VERSION 5.7 ;
  NOWIREEXTENSIONATPIN ON ;
  DIVIDERCHAR "/" ;
  BUSBITCHARS "[]" ;
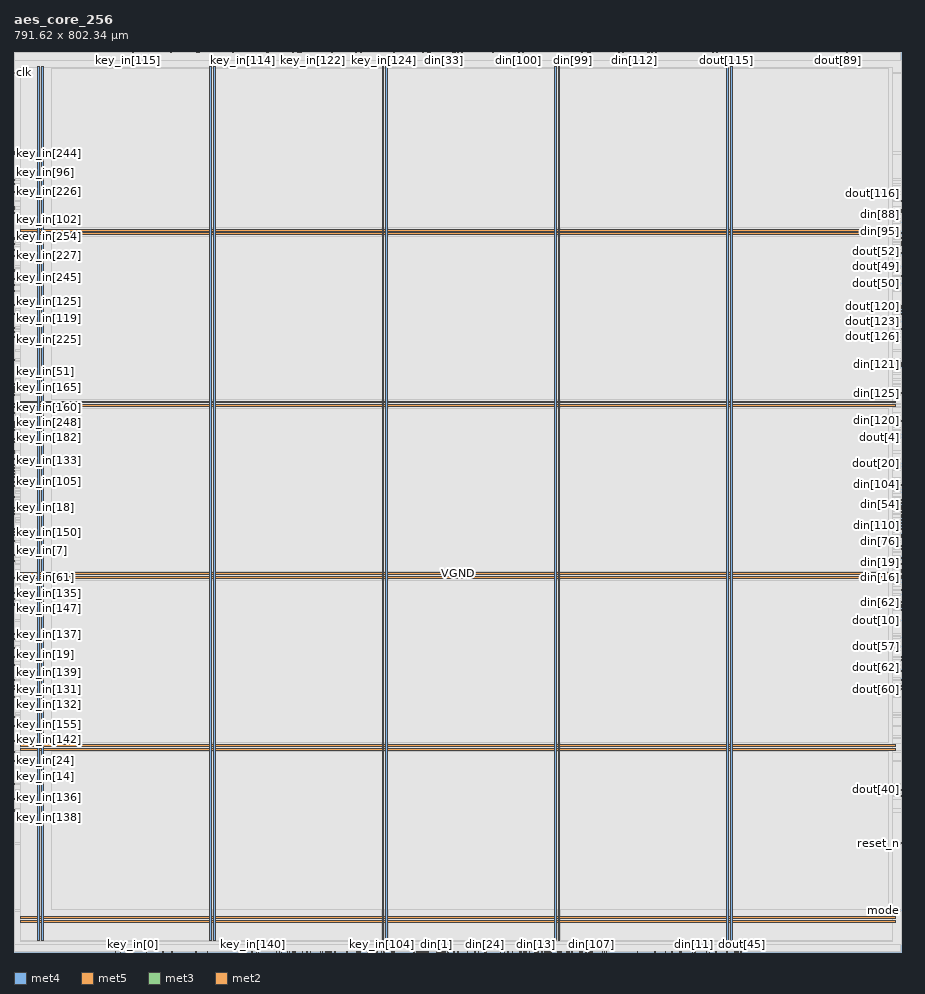
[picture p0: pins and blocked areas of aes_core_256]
MACRO aes_core_256
  CLASS BLOCK ;
  FOREIGN aes_core_256 ;
  ORIGIN 0.000 0.000 ;
  SIZE 791.620 BY 802.340 ;
  PIN VGND
    DIRECTION INOUT ;
    USE GROUND ;
    PORT
      LAYER met4 ;
        RECT 24.340 10.640 25.940 789.040 ;
    END
    PORT
      LAYER met4 ;
        RECT 177.940 10.640 179.540 789.040 ;
    END
    PORT
      LAYER met4 ;
        RECT 331.540 10.640 333.140 789.040 ;
    END
    PORT
      LAYER met4 ;
        RECT 485.140 10.640 486.740 789.040 ;
    END
    PORT
      LAYER met4 ;
        RECT 638.740 10.640 640.340 789.040 ;
    END
    PORT
      LAYER met5 ;
        RECT 5.520 30.030 785.680 31.630 ;
    END
    PORT
      LAYER met5 ;
        RECT 5.520 183.210 785.680 184.810 ;
    END
    PORT
      LAYER met5 ;
        RECT 5.520 336.390 785.680 337.990 ;
    END
    PORT
      LAYER met5 ;
        RECT 5.520 489.570 785.680 491.170 ;
    END
    PORT
      LAYER met5 ;
        RECT 5.520 642.750 785.680 644.350 ;
    END
  END VGND
  PIN VPWR
    DIRECTION INOUT ;
    USE POWER ;
    PORT
      LAYER met4 ;
        RECT 21.040 10.640 22.640 789.040 ;
    END
    PORT
      LAYER met4 ;
        RECT 174.640 10.640 176.240 789.040 ;
    END
    PORT
      LAYER met4 ;
        RECT 328.240 10.640 329.840 789.040 ;
    END
    PORT
      LAYER met4 ;
        RECT 481.840 10.640 483.440 789.040 ;
    END
    PORT
      LAYER met4 ;
        RECT 635.440 10.640 637.040 789.040 ;
    END
    PORT
      LAYER met5 ;
        RECT 5.520 26.730 785.680 28.330 ;
    END
    PORT
      LAYER met5 ;
        RECT 5.520 179.910 785.680 181.510 ;
    END
    PORT
      LAYER met5 ;
        RECT 5.520 333.090 785.680 334.690 ;
    END
    PORT
      LAYER met5 ;
        RECT 5.520 486.270 785.680 487.870 ;
    END
    PORT
      LAYER met5 ;
        RECT 5.520 639.450 785.680 641.050 ;
    END
  END VPWR
  PIN clk
    DIRECTION INPUT ;
    USE SIGNAL ;
    ANTENNAGATEAREA 0.852000 ;
    PORT
      LAYER met3 ;
        RECT 0.000 783.400 0.600 784.000 ;
    END
  END clk
  PIN din[0]
    DIRECTION INPUT ;
    USE SIGNAL ;
    ANTENNAGATEAREA 0.213000 ;
    PORT
      LAYER met2 ;
        RECT 392.010 0.000 392.290 0.280 ;
    END
  END din[0]
  PIN din[100]
    DIRECTION INPUT ;
    USE SIGNAL ;
    ANTENNAGATEAREA 0.213000 ;
    PORT
      LAYER met2 ;
        RECT 449.970 802.060 450.250 802.340 ;
    END
  END din[100]
  PIN din[101]
    DIRECTION INPUT ;
    USE SIGNAL ;
    ANTENNAGATEAREA 0.213000 ;
    PORT
      LAYER met2 ;
        RECT 418.690 802.060 418.970 802.340 ;
    END
  END din[101]
  PIN din[102]
    DIRECTION INPUT ;
    USE SIGNAL ;
    ANTENNAGATEAREA 0.213000 ;
    PORT
      LAYER met2 ;
        RECT 431.570 802.060 431.850 802.340 ;
    END
  END din[102]
  PIN din[103]
    DIRECTION INPUT ;
    USE SIGNAL ;
    ANTENNAGATEAREA 0.213000 ;
    PORT
      LAYER met2 ;
        RECT 432.490 802.060 432.770 802.340 ;
    END
  END din[103]
  PIN din[104]
    DIRECTION INPUT ;
    USE SIGNAL ;
    ANTENNAGATEAREA 0.213000 ;
    PORT
      LAYER met3 ;
        RECT 791.020 416.200 791.620 416.800 ;
    END
  END din[104]
  PIN din[105]
    DIRECTION INPUT ;
    USE SIGNAL ;
    ANTENNAGATEAREA 0.213000 ;
    PORT
      LAYER met3 ;
        RECT 791.020 409.400 791.620 410.000 ;
    END
  END din[105]
  PIN din[106]
    DIRECTION INPUT ;
    USE SIGNAL ;
    ANTENNAGATEAREA 0.213000 ;
    PORT
      LAYER met3 ;
        RECT 791.020 394.440 791.620 395.040 ;
    END
  END din[106]
  PIN din[107]
    DIRECTION INPUT ;
    USE SIGNAL ;
    ANTENNAGATEAREA 0.213000 ;
    PORT
      LAYER met2 ;
        RECT 514.370 0.000 514.650 0.280 ;
    END
  END din[107]
  PIN din[108]
    DIRECTION INPUT ;
    USE SIGNAL ;
    ANTENNAGATEAREA 0.213000 ;
    PORT
      LAYER met2 ;
        RECT 478.490 0.000 478.770 0.280 ;
    END
  END din[108]
  PIN din[109]
    DIRECTION INPUT ;
    USE SIGNAL ;
    ANTENNAGATEAREA 0.213000 ;
    PORT
      LAYER met2 ;
        RECT 505.170 0.000 505.450 0.280 ;
    END
  END din[109]
  PIN din[10]
    DIRECTION INPUT ;
    USE SIGNAL ;
    ANTENNAGATEAREA 0.213000 ;
    PORT
      LAYER met2 ;
        RECT 497.810 0.000 498.090 0.280 ;
    END
  END din[10]
  PIN din[110]
    DIRECTION INPUT ;
    USE SIGNAL ;
    ANTENNAGATEAREA 0.213000 ;
    PORT
      LAYER met3 ;
        RECT 791.020 379.480 791.620 380.080 ;
    END
  END din[110]
  PIN din[111]
    DIRECTION INPUT ;
    USE SIGNAL ;
    ANTENNAGATEAREA 0.213000 ;
    PORT
      LAYER met3 ;
        RECT 791.020 380.840 791.620 381.440 ;
    END
  END din[111]
  PIN din[112]
    DIRECTION INPUT ;
    USE SIGNAL ;
    ANTENNAGATEAREA 0.213000 ;
    PORT
      LAYER met2 ;
        RECT 553.010 802.060 553.290 802.340 ;
    END
  END din[112]
  PIN din[113]
    DIRECTION INPUT ;
    USE SIGNAL ;
    ANTENNAGATEAREA 0.213000 ;
    PORT
      LAYER met2 ;
        RECT 528.170 802.060 528.450 802.340 ;
    END
  END din[113]
  PIN din[114]
    DIRECTION INPUT ;
    USE SIGNAL ;
    ANTENNAGATEAREA 0.213000 ;
    PORT
      LAYER met2 ;
        RECT 518.970 802.060 519.250 802.340 ;
    END
  END din[114]
  PIN din[115]
    DIRECTION INPUT ;
    USE SIGNAL ;
    ANTENNAGATEAREA 0.213000 ;
    PORT
      LAYER met2 ;
        RECT 539.210 802.060 539.490 802.340 ;
    END
  END din[115]
  PIN din[116]
    DIRECTION INPUT ;
    USE SIGNAL ;
    ANTENNAGATEAREA 0.213000 ;
    PORT
      LAYER met2 ;
        RECT 511.610 802.060 511.890 802.340 ;
    END
  END din[116]
  PIN din[117]
    DIRECTION INPUT ;
    USE SIGNAL ;
    ANTENNAGATEAREA 0.213000 ;
    PORT
      LAYER met2 ;
        RECT 442.610 802.060 442.890 802.340 ;
    END
  END din[117]
  PIN din[118]
    DIRECTION INPUT ;
    USE SIGNAL ;
    ANTENNAGATEAREA 0.213000 ;
    PORT
      LAYER met2 ;
        RECT 533.690 802.060 533.970 802.340 ;
    END
  END din[118]
  PIN din[119]
    DIRECTION INPUT ;
    USE SIGNAL ;
    ANTENNAGATEAREA 0.213000 ;
    PORT
      LAYER met2 ;
        RECT 444.450 802.060 444.730 802.340 ;
    END
  END din[119]
  PIN din[11]
    DIRECTION INPUT ;
    USE SIGNAL ;
    ANTENNAGATEAREA 0.213000 ;
    PORT
      LAYER met2 ;
        RECT 606.370 0.000 606.650 0.280 ;
    END
  END din[11]
  PIN din[120]
    DIRECTION INPUT ;
    USE SIGNAL ;
    ANTENNAGATEAREA 0.213000 ;
    PORT
      LAYER met3 ;
        RECT 791.020 473.320 791.620 473.920 ;
    END
  END din[120]
  PIN din[121]
    DIRECTION INPUT ;
    USE SIGNAL ;
    ANTENNAGATEAREA 0.213000 ;
    PORT
      LAYER met3 ;
        RECT 791.020 523.640 791.620 524.240 ;
    END
  END din[121]
  PIN din[122]
    DIRECTION INPUT ;
    USE SIGNAL ;
    ANTENNAGATEAREA 0.213000 ;
    PORT
      LAYER met3 ;
        RECT 791.020 461.080 791.620 461.680 ;
    END
  END din[122]
  PIN din[123]
    DIRECTION INPUT ;
    USE SIGNAL ;
    ANTENNAGATEAREA 0.213000 ;
    PORT
      LAYER met2 ;
        RECT 546.570 802.060 546.850 802.340 ;
    END
  END din[123]
  PIN din[124]
    DIRECTION INPUT ;
    USE SIGNAL ;
    ANTENNAGATEAREA 0.213000 ;
    PORT
      LAYER met3 ;
        RECT 791.020 522.280 791.620 522.880 ;
    END
  END din[124]
  PIN din[125]
    DIRECTION INPUT ;
    USE SIGNAL ;
    ANTENNAGATEAREA 0.213000 ;
    PORT
      LAYER met3 ;
        RECT 791.020 497.800 791.620 498.400 ;
    END
  END din[125]
  PIN din[126]
    DIRECTION INPUT ;
    USE SIGNAL ;
    ANTENNAGATEAREA 0.213000 ;
    PORT
      LAYER met2 ;
        RECT 513.450 802.060 513.730 802.340 ;
    END
  END din[126]
  PIN din[127]
    DIRECTION INPUT ;
    USE SIGNAL ;
    ANTENNAGATEAREA 0.213000 ;
    PORT
      LAYER met3 ;
        RECT 791.020 520.920 791.620 521.520 ;
    END
  END din[127]
  PIN din[12]
    DIRECTION INPUT ;
    USE SIGNAL ;
    ANTENNAGATEAREA 0.213000 ;
    PORT
      LAYER met2 ;
        RECT 634.890 0.000 635.170 0.280 ;
    END
  END din[12]
  PIN din[13]
    DIRECTION INPUT ;
    USE SIGNAL ;
    ANTENNAGATEAREA 0.213000 ;
    PORT
      LAYER met2 ;
        RECT 465.610 0.000 465.890 0.280 ;
    END
  END din[13]
  PIN din[14]
    DIRECTION INPUT ;
    USE SIGNAL ;
    ANTENNAGATEAREA 0.213000 ;
    PORT
      LAYER met2 ;
        RECT 493.210 0.000 493.490 0.280 ;
    END
  END din[14]
  PIN din[15]
    DIRECTION INPUT ;
    USE SIGNAL ;
    ANTENNAGATEAREA 0.213000 ;
    PORT
      LAYER met2 ;
        RECT 484.930 0.000 485.210 0.280 ;
    END
  END din[15]
  PIN din[16]
    DIRECTION INPUT ;
    USE SIGNAL ;
    ANTENNAGATEAREA 0.213000 ;
    PORT
      LAYER met3 ;
        RECT 791.020 333.240 791.620 333.840 ;
    END
  END din[16]
  PIN din[17]
    DIRECTION INPUT ;
    USE SIGNAL ;
    ANTENNAGATEAREA 0.213000 ;
    PORT
      LAYER met2 ;
        RECT 473.890 0.000 474.170 0.280 ;
    END
  END din[17]
  PIN din[18]
    DIRECTION INPUT ;
    USE SIGNAL ;
    ANTENNAGATEAREA 0.213000 ;
    PORT
      LAYER met2 ;
        RECT 414.090 0.000 414.370 0.280 ;
    END
  END din[18]
  PIN din[19]
    DIRECTION INPUT ;
    USE SIGNAL ;
    ANTENNAGATEAREA 0.213000 ;
    PORT
      LAYER met3 ;
        RECT 791.020 340.040 791.620 340.640 ;
    END
  END din[19]
  PIN din[1]
    DIRECTION INPUT ;
    USE SIGNAL ;
    ANTENNAGATEAREA 0.213000 ;
    PORT
      LAYER met2 ;
        RECT 376.370 0.000 376.650 0.280 ;
    END
  END din[1]
  PIN din[20]
    DIRECTION INPUT ;
    USE SIGNAL ;
    ANTENNAGATEAREA 0.213000 ;
    PORT
      LAYER met3 ;
        RECT 791.020 345.480 791.620 346.080 ;
    END
  END din[20]
  PIN din[21]
    DIRECTION INPUT ;
    USE SIGNAL ;
    ANTENNAGATEAREA 0.213000 ;
    PORT
      LAYER met2 ;
        RECT 450.890 0.000 451.170 0.280 ;
    END
  END din[21]
  PIN din[22]
    DIRECTION INPUT ;
    USE SIGNAL ;
    ANTENNAGATEAREA 0.213000 ;
    PORT
      LAYER met3 ;
        RECT 791.020 307.400 791.620 308.000 ;
    END
  END din[22]
  PIN din[23]
    DIRECTION INPUT ;
    USE SIGNAL ;
    ANTENNAGATEAREA 0.213000 ;
    PORT
      LAYER met3 ;
        RECT 791.020 350.920 791.620 351.520 ;
    END
  END din[23]
  PIN din[24]
    DIRECTION INPUT ;
    USE SIGNAL ;
    ANTENNAGATEAREA 0.213000 ;
    PORT
      LAYER met2 ;
        RECT 419.610 0.000 419.890 0.280 ;
    END
  END din[24]
  PIN din[25]
    DIRECTION INPUT ;
    USE SIGNAL ;
    ANTENNAGATEAREA 0.213000 ;
    PORT
      LAYER met2 ;
        RECT 410.410 0.000 410.690 0.280 ;
    END
  END din[25]
  PIN din[26]
    DIRECTION INPUT ;
    USE SIGNAL ;
    ANTENNAGATEAREA 0.213000 ;
    PORT
      LAYER met2 ;
        RECT 433.410 0.000 433.690 0.280 ;
    END
  END din[26]
  PIN din[27]
    DIRECTION INPUT ;
    USE SIGNAL ;
    ANTENNAGATEAREA 0.213000 ;
    PORT
      LAYER met2 ;
        RECT 474.810 0.000 475.090 0.280 ;
    END
  END din[27]
  PIN din[28]
    DIRECTION INPUT ;
    USE SIGNAL ;
    ANTENNAGATEAREA 0.213000 ;
    PORT
      LAYER met2 ;
        RECT 459.170 0.000 459.450 0.280 ;
    END
  END din[28]
  PIN din[29]
    DIRECTION INPUT ;
    USE SIGNAL ;
    ANTENNAGATEAREA 0.213000 ;
    PORT
      LAYER met2 ;
        RECT 444.450 0.000 444.730 0.280 ;
    END
  END din[29]
  PIN din[2]
    DIRECTION INPUT ;
    USE SIGNAL ;
    ANTENNAGATEAREA 0.213000 ;
    PORT
      LAYER met2 ;
        RECT 377.290 0.000 377.570 0.280 ;
    END
  END din[2]
  PIN din[30]
    DIRECTION INPUT ;
    USE SIGNAL ;
    ANTENNAGATEAREA 0.213000 ;
    PORT
      LAYER met2 ;
        RECT 378.210 0.000 378.490 0.280 ;
    END
  END din[30]
  PIN din[31]
    DIRECTION INPUT ;
    USE SIGNAL ;
    ANTENNAGATEAREA 0.213000 ;
    PORT
      LAYER met2 ;
        RECT 386.490 0.000 386.770 0.280 ;
    END
  END din[31]
  PIN din[32]
    DIRECTION INPUT ;
    USE SIGNAL ;
    ANTENNAGATEAREA 0.213000 ;
    PORT
      LAYER met3 ;
        RECT 791.020 398.520 791.620 399.120 ;
    END
  END din[32]
  PIN din[33]
    DIRECTION INPUT ;
    USE SIGNAL ;
    ANTENNAGATEAREA 0.213000 ;
    PORT
      LAYER met2 ;
        RECT 382.810 802.060 383.090 802.340 ;
    END
  END din[33]
  PIN din[34]
    DIRECTION INPUT ;
    USE SIGNAL ;
    ANTENNAGATEAREA 0.213000 ;
    PORT
      LAYER met2 ;
        RECT 380.050 802.060 380.330 802.340 ;
    END
  END din[34]
  PIN din[35]
    DIRECTION INPUT ;
    USE SIGNAL ;
    ANTENNAGATEAREA 0.213000 ;
    PORT
      LAYER met3 ;
        RECT 791.020 376.760 791.620 377.360 ;
    END
  END din[35]
  PIN din[36]
    DIRECTION INPUT ;
    USE SIGNAL ;
    ANTENNAGATEAREA 0.213000 ;
    PORT
      LAYER met2 ;
        RECT 392.010 802.060 392.290 802.340 ;
    END
  END din[36]
  PIN din[37]
    DIRECTION INPUT ;
    USE SIGNAL ;
    ANTENNAGATEAREA 0.213000 ;
    PORT
      LAYER met2 ;
        RECT 451.810 0.000 452.090 0.280 ;
    END
  END din[37]
  PIN din[38]
    DIRECTION INPUT ;
    USE SIGNAL ;
    ANTENNAGATEAREA 0.213000 ;
    PORT
      LAYER met2 ;
        RECT 392.930 802.060 393.210 802.340 ;
    END
  END din[38]
  PIN din[39]
    DIRECTION INPUT ;
    USE SIGNAL ;
    ANTENNAGATEAREA 0.213000 ;
    PORT
      LAYER met2 ;
        RECT 400.290 802.060 400.570 802.340 ;
    END
  END din[39]
  PIN din[3]
    DIRECTION INPUT ;
    USE SIGNAL ;
    ANTENNAGATEAREA 0.213000 ;
    PORT
      LAYER met2 ;
        RECT 380.970 0.000 381.250 0.280 ;
    END
  END din[3]
  PIN din[40]
    DIRECTION INPUT ;
    USE SIGNAL ;
    ANTENNAGATEAREA 0.213000 ;
    PORT
      LAYER met2 ;
        RECT 580.610 0.000 580.890 0.280 ;
    END
  END din[40]
  PIN din[41]
    DIRECTION INPUT ;
    USE SIGNAL ;
    ANTENNAGATEAREA 0.213000 ;
    PORT
      LAYER met2 ;
        RECT 555.770 0.000 556.050 0.280 ;
    END
  END din[41]
  PIN din[42]
    DIRECTION INPUT ;
    USE SIGNAL ;
    ANTENNAGATEAREA 0.213000 ;
    PORT
      LAYER met2 ;
        RECT 528.170 0.000 528.450 0.280 ;
    END
  END din[42]
  PIN din[43]
    DIRECTION INPUT ;
    USE SIGNAL ;
    ANTENNAGATEAREA 0.213000 ;
    PORT
      LAYER met2 ;
        RECT 604.530 0.000 604.810 0.280 ;
    END
  END din[43]
  PIN din[44]
    DIRECTION INPUT ;
    USE SIGNAL ;
    ANTENNAGATEAREA 0.213000 ;
    PORT
      LAYER met2 ;
        RECT 594.410 0.000 594.690 0.280 ;
    END
  END din[44]
  PIN din[45]
    DIRECTION INPUT ;
    USE SIGNAL ;
    ANTENNAGATEAREA 0.213000 ;
    PORT
      LAYER met2 ;
        RECT 617.410 0.000 617.690 0.280 ;
    END
  END din[45]
  PIN din[46]
    DIRECTION INPUT ;
    USE SIGNAL ;
    ANTENNAGATEAREA 0.213000 ;
    PORT
      LAYER met2 ;
        RECT 494.130 0.000 494.410 0.280 ;
    END
  END din[46]
  PIN din[47]
    DIRECTION INPUT ;
    USE SIGNAL ;
    ANTENNAGATEAREA 0.213000 ;
    PORT
      LAYER met2 ;
        RECT 495.050 0.000 495.330 0.280 ;
    END
  END din[47]
  PIN din[48]
    DIRECTION INPUT ;
    USE SIGNAL ;
    ANTENNAGATEAREA 0.213000 ;
    PORT
      LAYER met2 ;
        RECT 564.970 802.060 565.250 802.340 ;
    END
  END din[48]
  PIN din[49]
    DIRECTION INPUT ;
    USE SIGNAL ;
    ANTENNAGATEAREA 0.213000 ;
    PORT
      LAYER met3 ;
        RECT 791.020 378.120 791.620 378.720 ;
    END
  END din[49]
  PIN din[4]
    DIRECTION INPUT ;
    USE SIGNAL ;
    ANTENNAGATEAREA 0.213000 ;
    PORT
      LAYER met2 ;
        RECT 420.530 0.000 420.810 0.280 ;
    END
  END din[4]
  PIN din[50]
    DIRECTION INPUT ;
    USE SIGNAL ;
    ANTENNAGATEAREA 0.213000 ;
    PORT
      LAYER met3 ;
        RECT 791.020 525.000 791.620 525.600 ;
    END
  END din[50]
  PIN din[51]
    DIRECTION INPUT ;
    USE SIGNAL ;
    ANTENNAGATEAREA 0.213000 ;
    PORT
      LAYER met3 ;
        RECT 791.020 383.560 791.620 384.160 ;
    END
  END din[51]
  PIN din[52]
    DIRECTION INPUT ;
    USE SIGNAL ;
    ANTENNAGATEAREA 0.213000 ;
    PORT
      LAYER met2 ;
        RECT 576.010 802.060 576.290 802.340 ;
    END
  END din[52]
  PIN din[53]
    DIRECTION INPUT ;
    USE SIGNAL ;
    ANTENNAGATEAREA 0.213000 ;
    PORT
      LAYER met3 ;
        RECT 791.020 399.880 791.620 400.480 ;
    END
  END din[53]
  PIN din[54]
    DIRECTION INPUT ;
    USE SIGNAL ;
    ANTENNAGATEAREA 0.213000 ;
    PORT
      LAYER met3 ;
        RECT 791.020 391.720 791.620 392.320 ;
    END
  END din[54]
  PIN din[55]
    DIRECTION INPUT ;
    USE SIGNAL ;
    ANTENNAGATEAREA 0.213000 ;
    PORT
      LAYER met2 ;
        RECT 542.890 802.060 543.170 802.340 ;
    END
  END din[55]
  PIN din[56]
    DIRECTION INPUT ;
    USE SIGNAL ;
    ANTENNAGATEAREA 0.213000 ;
    PORT
      LAYER met2 ;
        RECT 625.690 0.000 625.970 0.280 ;
    END
  END din[56]
  PIN din[57]
    DIRECTION INPUT ;
    USE SIGNAL ;
    ANTENNAGATEAREA 0.213000 ;
    PORT
      LAYER met2 ;
        RECT 524.490 0.000 524.770 0.280 ;
    END
  END din[57]
  PIN din[58]
    DIRECTION INPUT ;
    USE SIGNAL ;
    ANTENNAGATEAREA 0.213000 ;
    PORT
      LAYER met2 ;
        RECT 526.330 0.000 526.610 0.280 ;
    END
  END din[58]
  PIN din[59]
    DIRECTION INPUT ;
    USE SIGNAL ;
    ANTENNAGATEAREA 0.213000 ;
    PORT
      LAYER met3 ;
        RECT 791.020 352.280 791.620 352.880 ;
    END
  END din[59]
  PIN din[5]
    DIRECTION INPUT ;
    USE SIGNAL ;
    ANTENNAGATEAREA 0.213000 ;
    PORT
      LAYER met2 ;
        RECT 437.090 0.000 437.370 0.280 ;
    END
  END din[5]
  PIN din[60]
    DIRECTION INPUT ;
    USE SIGNAL ;
    ANTENNAGATEAREA 0.213000 ;
    PORT
      LAYER met2 ;
        RECT 512.530 0.000 512.810 0.280 ;
    END
  END din[60]
  PIN din[61]
    DIRECTION INPUT ;
    USE SIGNAL ;
    ANTENNAGATEAREA 0.213000 ;
    PORT
      LAYER met2 ;
        RECT 515.290 0.000 515.570 0.280 ;
    END
  END din[61]
  PIN din[62]
    DIRECTION INPUT ;
    USE SIGNAL ;
    ANTENNAGATEAREA 0.213000 ;
    PORT
      LAYER met3 ;
        RECT 791.020 311.480 791.620 312.080 ;
    END
  END din[62]
  PIN din[63]
    DIRECTION INPUT ;
    USE SIGNAL ;
    ANTENNAGATEAREA 0.213000 ;
    PORT
      LAYER met2 ;
        RECT 509.770 0.000 510.050 0.280 ;
    END
  END din[63]
  PIN din[64]
    DIRECTION INPUT ;
    USE SIGNAL ;
    ANTENNAGATEAREA 0.213000 ;
    PORT
      LAYER met2 ;
        RECT 414.090 802.060 414.370 802.340 ;
    END
  END din[64]
  PIN din[65]
    DIRECTION INPUT ;
    USE SIGNAL ;
    ANTENNAGATEAREA 0.213000 ;
    PORT
      LAYER met2 ;
        RECT 405.810 802.060 406.090 802.340 ;
    END
  END din[65]
  PIN din[66]
    DIRECTION INPUT ;
    USE SIGNAL ;
    ANTENNAGATEAREA 0.213000 ;
    PORT
      LAYER met2 ;
        RECT 413.170 802.060 413.450 802.340 ;
    END
  END din[66]
  PIN din[67]
    DIRECTION INPUT ;
    USE SIGNAL ;
    ANTENNAGATEAREA 0.213000 ;
    PORT
      LAYER met2 ;
        RECT 403.050 802.060 403.330 802.340 ;
    END
  END din[67]
  PIN din[68]
    DIRECTION INPUT ;
    USE SIGNAL ;
    ANTENNAGATEAREA 0.213000 ;
    PORT
      LAYER met2 ;
        RECT 438.930 802.060 439.210 802.340 ;
    END
  END din[68]
  PIN din[69]
    DIRECTION INPUT ;
    USE SIGNAL ;
    ANTENNAGATEAREA 0.213000 ;
    PORT
      LAYER met2 ;
        RECT 436.170 802.060 436.450 802.340 ;
    END
  END din[69]
  PIN din[6]
    DIRECTION INPUT ;
    USE SIGNAL ;
    ANTENNAGATEAREA 0.213000 ;
    PORT
      LAYER met2 ;
        RECT 379.130 0.000 379.410 0.280 ;
    END
  END din[6]
  PIN din[70]
    DIRECTION INPUT ;
    USE SIGNAL ;
    ANTENNAGATEAREA 0.213000 ;
    PORT
      LAYER met2 ;
        RECT 416.850 802.060 417.130 802.340 ;
    END
  END din[70]
  PIN din[71]
    DIRECTION INPUT ;
    USE SIGNAL ;
    ANTENNAGATEAREA 0.213000 ;
    PORT
      LAYER met2 ;
        RECT 426.970 802.060 427.250 802.340 ;
    END
  END din[71]
  PIN din[72]
    DIRECTION INPUT ;
    USE SIGNAL ;
    ANTENNAGATEAREA 0.213000 ;
    PORT
      LAYER met2 ;
        RECT 455.490 0.000 455.770 0.280 ;
    END
  END din[72]
  PIN din[73]
    DIRECTION INPUT ;
    USE SIGNAL ;
    ANTENNAGATEAREA 0.213000 ;
    PORT
      LAYER met3 ;
        RECT 791.020 386.280 791.620 386.880 ;
    END
  END din[73]
  PIN din[74]
    DIRECTION INPUT ;
    USE SIGNAL ;
    ANTENNAGATEAREA 0.213000 ;
    PORT
      LAYER met3 ;
        RECT 791.020 382.200 791.620 382.800 ;
    END
  END din[74]
  PIN din[75]
    DIRECTION INPUT ;
    USE SIGNAL ;
    ANTENNAGATEAREA 0.213000 ;
    PORT
      LAYER met3 ;
        RECT 791.020 402.600 791.620 403.200 ;
    END
  END din[75]
  PIN din[76]
    DIRECTION INPUT ;
    USE SIGNAL ;
    ANTENNAGATEAREA 0.213000 ;
    PORT
      LAYER met3 ;
        RECT 791.020 372.680 791.620 373.280 ;
    END
  END din[76]
  PIN din[77]
    DIRECTION INPUT ;
    USE SIGNAL ;
    ANTENNAGATEAREA 0.213000 ;
    PORT
      LAYER met2 ;
        RECT 492.290 0.000 492.570 0.280 ;
    END
  END din[77]
  PIN din[78]
    DIRECTION INPUT ;
    USE SIGNAL ;
    ANTENNAGATEAREA 0.213000 ;
    PORT
      LAYER met2 ;
        RECT 463.770 0.000 464.050 0.280 ;
    END
  END din[78]
  PIN din[79]
    DIRECTION INPUT ;
    USE SIGNAL ;
    ANTENNAGATEAREA 0.213000 ;
    PORT
      LAYER met2 ;
        RECT 472.970 0.000 473.250 0.280 ;
    END
  END din[79]
  PIN din[7]
    DIRECTION INPUT ;
    USE SIGNAL ;
    ANTENNAGATEAREA 0.213000 ;
    PORT
      LAYER met2 ;
        RECT 380.050 0.000 380.330 0.280 ;
    END
  END din[7]
  PIN din[80]
    DIRECTION INPUT ;
    USE SIGNAL ;
    ANTENNAGATEAREA 0.213000 ;
    PORT
      LAYER met2 ;
        RECT 560.370 802.060 560.650 802.340 ;
    END
  END din[80]
  PIN din[81]
    DIRECTION INPUT ;
    USE SIGNAL ;
    ANTENNAGATEAREA 0.213000 ;
    PORT
      LAYER met2 ;
        RECT 543.810 802.060 544.090 802.340 ;
    END
  END din[81]
  PIN din[82]
    DIRECTION INPUT ;
    USE SIGNAL ;
    ANTENNAGATEAREA 0.213000 ;
    PORT
      LAYER met2 ;
        RECT 557.610 802.060 557.890 802.340 ;
    END
  END din[82]
  PIN din[83]
    DIRECTION INPUT ;
    USE SIGNAL ;
    ANTENNAGATEAREA 0.213000 ;
    PORT
      LAYER met2 ;
        RECT 558.530 802.060 558.810 802.340 ;
    END
  END din[83]
  PIN din[84]
    DIRECTION INPUT ;
    USE SIGNAL ;
    ANTENNAGATEAREA 0.213000 ;
    PORT
      LAYER met2 ;
        RECT 547.490 802.060 547.770 802.340 ;
    END
  END din[84]
  PIN din[85]
    DIRECTION INPUT ;
    USE SIGNAL ;
    ANTENNAGATEAREA 0.213000 ;
    PORT
      LAYER met2 ;
        RECT 472.050 802.060 472.330 802.340 ;
    END
  END din[85]
  PIN din[86]
    DIRECTION INPUT ;
    USE SIGNAL ;
    ANTENNAGATEAREA 0.213000 ;
    PORT
      LAYER met2 ;
        RECT 559.450 802.060 559.730 802.340 ;
    END
  END din[86]
  PIN din[87]
    DIRECTION INPUT ;
    USE SIGNAL ;
    ANTENNAGATEAREA 0.213000 ;
    PORT
      LAYER met2 ;
        RECT 556.690 802.060 556.970 802.340 ;
    END
  END din[87]
  PIN din[88]
    DIRECTION INPUT ;
    USE SIGNAL ;
    ANTENNAGATEAREA 0.213000 ;
    PORT
      LAYER met3 ;
        RECT 791.020 650.120 791.620 650.720 ;
    END
  END din[88]
  PIN din[89]
    DIRECTION INPUT ;
    USE SIGNAL ;
    ANTENNAGATEAREA 0.213000 ;
    PORT
      LAYER met2 ;
        RECT 587.050 802.060 587.330 802.340 ;
    END
  END din[89]
  PIN din[8]
    DIRECTION INPUT ;
    USE SIGNAL ;
    ANTENNAGATEAREA 0.213000 ;
    PORT
      LAYER met2 ;
        RECT 476.650 0.000 476.930 0.280 ;
    END
  END din[8]
  PIN din[90]
    DIRECTION INPUT ;
    USE SIGNAL ;
    ANTENNAGATEAREA 0.213000 ;
    PORT
      LAYER met2 ;
        RECT 582.450 802.060 582.730 802.340 ;
    END
  END din[90]
  PIN din[91]
    DIRECTION INPUT ;
    USE SIGNAL ;
    ANTENNAGATEAREA 0.213000 ;
    PORT
      LAYER met2 ;
        RECT 568.650 802.060 568.930 802.340 ;
    END
  END din[91]
  PIN din[92]
    DIRECTION INPUT ;
    USE SIGNAL ;
    ANTENNAGATEAREA 0.213000 ;
    PORT
      LAYER met3 ;
        RECT 791.020 659.640 791.620 660.240 ;
    END
  END din[92]
  PIN din[93]
    DIRECTION INPUT ;
    USE SIGNAL ;
    ANTENNAGATEAREA 0.213000 ;
    PORT
      LAYER met3 ;
        RECT 791.020 661.000 791.620 661.600 ;
    END
  END din[93]
  PIN din[94]
    DIRECTION INPUT ;
    USE SIGNAL ;
    ANTENNAGATEAREA 0.213000 ;
    PORT
      LAYER met2 ;
        RECT 565.890 802.060 566.170 802.340 ;
    END
  END din[94]
  PIN din[95]
    DIRECTION INPUT ;
    USE SIGNAL ;
    ANTENNAGATEAREA 0.213000 ;
    PORT
      LAYER met3 ;
        RECT 791.020 641.960 791.620 642.560 ;
    END
  END din[95]
  PIN din[96]
    DIRECTION INPUT ;
    USE SIGNAL ;
    ANTENNAGATEAREA 0.213000 ;
    PORT
      LAYER met2 ;
        RECT 470.210 802.060 470.490 802.340 ;
    END
  END din[96]
  PIN din[97]
    DIRECTION INPUT ;
    USE SIGNAL ;
    ANTENNAGATEAREA 0.213000 ;
    PORT
      LAYER met2 ;
        RECT 453.650 802.060 453.930 802.340 ;
    END
  END din[97]
  PIN din[98]
    DIRECTION INPUT ;
    USE SIGNAL ;
    ANTENNAGATEAREA 0.213000 ;
    PORT
      LAYER met2 ;
        RECT 458.250 802.060 458.530 802.340 ;
    END
  END din[98]
  PIN din[99]
    DIRECTION INPUT ;
    USE SIGNAL ;
    ANTENNAGATEAREA 0.213000 ;
    PORT
      LAYER met2 ;
        RECT 497.810 802.060 498.090 802.340 ;
    END
  END din[99]
  PIN din[9]
    DIRECTION INPUT ;
    USE SIGNAL ;
    ANTENNAGATEAREA 0.213000 ;
    PORT
      LAYER met2 ;
        RECT 475.730 0.000 476.010 0.280 ;
    END
  END din[9]
  PIN done
    DIRECTION OUTPUT ;
    USE SIGNAL ;
    ANTENNADIFFAREA 0.702900 ;
    PORT
      LAYER met2 ;
        RECT 395.690 0.000 395.970 0.280 ;
    END
  END done
  PIN dout[0]
    DIRECTION OUTPUT ;
    USE SIGNAL ;
    ANTENNADIFFAREA 0.702900 ;
    PORT
      LAYER met2 ;
        RECT 355.210 802.060 355.490 802.340 ;
    END
  END dout[0]
  PIN dout[100]
    DIRECTION OUTPUT ;
    USE SIGNAL ;
    ANTENNADIFFAREA 0.702900 ;
    PORT
      LAYER met2 ;
        RECT 415.930 802.060 416.210 802.340 ;
    END
  END dout[100]
  PIN dout[101]
    DIRECTION OUTPUT ;
    USE SIGNAL ;
    ANTENNADIFFAREA 0.702900 ;
    PORT
      LAYER met2 ;
        RECT 521.730 802.060 522.010 802.340 ;
    END
  END dout[101]
  PIN dout[102]
    DIRECTION OUTPUT ;
    USE SIGNAL ;
    ANTENNADIFFAREA 0.702900 ;
    PORT
      LAYER met2 ;
        RECT 404.890 802.060 405.170 802.340 ;
    END
  END dout[102]
  PIN dout[103]
    DIRECTION OUTPUT ;
    USE SIGNAL ;
    ANTENNADIFFAREA 0.702900 ;
    PORT
      LAYER met2 ;
        RECT 409.490 802.060 409.770 802.340 ;
    END
  END dout[103]
  PIN dout[104]
    DIRECTION OUTPUT ;
    USE SIGNAL ;
    ANTENNADIFFAREA 0.702900 ;
    PORT
      LAYER met3 ;
        RECT 791.020 369.960 791.620 370.560 ;
    END
  END dout[104]
  PIN dout[105]
    DIRECTION OUTPUT ;
    USE SIGNAL ;
    ANTENNADIFFAREA 0.702900 ;
    PORT
      LAYER met3 ;
        RECT 791.020 280.200 791.620 280.800 ;
    END
  END dout[105]
  PIN dout[106]
    DIRECTION OUTPUT ;
    USE SIGNAL ;
    ANTENNADIFFAREA 0.702900 ;
    PORT
      LAYER met3 ;
        RECT 791.020 371.320 791.620 371.920 ;
    END
  END dout[106]
  PIN dout[107]
    DIRECTION OUTPUT ;
    USE SIGNAL ;
    ANTENNADIFFAREA 0.702900 ;
    PORT
      LAYER met2 ;
        RECT 644.090 0.000 644.370 0.280 ;
    END
  END dout[107]
  PIN dout[108]
    DIRECTION OUTPUT ;
    USE SIGNAL ;
    ANTENNADIFFAREA 0.702900 ;
    PORT
      LAYER met2 ;
        RECT 504.250 0.000 504.530 0.280 ;
    END
  END dout[108]
  PIN dout[109]
    DIRECTION OUTPUT ;
    USE SIGNAL ;
    ANTENNADIFFAREA 0.702900 ;
    PORT
      LAYER met2 ;
        RECT 506.090 0.000 506.370 0.280 ;
    END
  END dout[109]
  PIN dout[10]
    DIRECTION OUTPUT ;
    USE SIGNAL ;
    ANTENNADIFFAREA 0.702900 ;
    PORT
      LAYER met3 ;
        RECT 791.020 295.160 791.620 295.760 ;
    END
  END dout[10]
  PIN dout[110]
    DIRECTION OUTPUT ;
    USE SIGNAL ;
    ANTENNADIFFAREA 0.702900 ;
    PORT
      LAYER met3 ;
        RECT 791.020 359.080 791.620 359.680 ;
    END
  END dout[110]
  PIN dout[111]
    DIRECTION OUTPUT ;
    USE SIGNAL ;
    ANTENNADIFFAREA 0.702900 ;
    PORT
      LAYER met3 ;
        RECT 791.020 361.800 791.620 362.400 ;
    END
  END dout[111]
  PIN dout[112]
    DIRECTION OUTPUT ;
    USE SIGNAL ;
    ANTENNADIFFAREA 0.702900 ;
    PORT
      LAYER met2 ;
        RECT 522.650 802.060 522.930 802.340 ;
    END
  END dout[112]
  PIN dout[113]
    DIRECTION OUTPUT ;
    USE SIGNAL ;
    ANTENNADIFFAREA 0.702900 ;
    PORT
      LAYER met2 ;
        RECT 622.930 802.060 623.210 802.340 ;
    END
  END dout[113]
  PIN dout[114]
    DIRECTION OUTPUT ;
    USE SIGNAL ;
    ANTENNADIFFAREA 0.702900 ;
    PORT
      LAYER met2 ;
        RECT 530.930 802.060 531.210 802.340 ;
    END
  END dout[114]
  PIN dout[115]
    DIRECTION OUTPUT ;
    USE SIGNAL ;
    ANTENNADIFFAREA 0.702900 ;
    PORT
      LAYER met2 ;
        RECT 634.890 802.060 635.170 802.340 ;
    END
  END dout[115]
  PIN dout[116]
    DIRECTION OUTPUT ;
    USE SIGNAL ;
    ANTENNADIFFAREA 0.702900 ;
    PORT
      LAYER met3 ;
        RECT 791.020 669.160 791.620 669.760 ;
    END
  END dout[116]
  PIN dout[117]
    DIRECTION OUTPUT ;
    USE SIGNAL ;
    ANTENNADIFFAREA 0.702900 ;
    PORT
      LAYER met2 ;
        RECT 637.650 802.060 637.930 802.340 ;
    END
  END dout[117]
  PIN dout[118]
    DIRECTION OUTPUT ;
    USE SIGNAL ;
    ANTENNADIFFAREA 0.702900 ;
    PORT
      LAYER met2 ;
        RECT 626.610 802.060 626.890 802.340 ;
    END
  END dout[118]
  PIN dout[119]
    DIRECTION OUTPUT ;
    USE SIGNAL ;
    ANTENNADIFFAREA 0.702900 ;
    PORT
      LAYER met2 ;
        RECT 635.810 802.060 636.090 802.340 ;
    END
  END dout[119]
  PIN dout[11]
    DIRECTION OUTPUT ;
    USE SIGNAL ;
    ANTENNADIFFAREA 0.702900 ;
    PORT
      LAYER met3 ;
        RECT 791.020 243.480 791.620 244.080 ;
    END
  END dout[11]
  PIN dout[120]
    DIRECTION OUTPUT ;
    USE SIGNAL ;
    ANTENNADIFFAREA 0.702900 ;
    PORT
      LAYER met3 ;
        RECT 791.020 575.320 791.620 575.920 ;
    END
  END dout[120]
  PIN dout[121]
    DIRECTION OUTPUT ;
    USE SIGNAL ;
    ANTENNADIFFAREA 0.702900 ;
    PORT
      LAYER met3 ;
        RECT 791.020 572.600 791.620 573.200 ;
    END
  END dout[121]
  PIN dout[122]
    DIRECTION OUTPUT ;
    USE SIGNAL ;
    ANTENNADIFFAREA 0.702900 ;
    PORT
      LAYER met3 ;
        RECT 791.020 573.960 791.620 574.560 ;
    END
  END dout[122]
  PIN dout[123]
    DIRECTION OUTPUT ;
    USE SIGNAL ;
    ANTENNADIFFAREA 0.702900 ;
    PORT
      LAYER met3 ;
        RECT 791.020 561.720 791.620 562.320 ;
    END
  END dout[123]
  PIN dout[124]
    DIRECTION OUTPUT ;
    USE SIGNAL ;
    ANTENNADIFFAREA 0.702900 ;
    PORT
      LAYER met3 ;
        RECT 791.020 571.240 791.620 571.840 ;
    END
  END dout[124]
  PIN dout[125]
    DIRECTION OUTPUT ;
    USE SIGNAL ;
    ANTENNADIFFAREA 0.702900 ;
    PORT
      LAYER met3 ;
        RECT 791.020 568.520 791.620 569.120 ;
    END
  END dout[125]
  PIN dout[126]
    DIRECTION OUTPUT ;
    USE SIGNAL ;
    ANTENNADIFFAREA 0.702900 ;
    PORT
      LAYER met3 ;
        RECT 791.020 554.920 791.620 555.520 ;
    END
  END dout[126]
  PIN dout[127]
    DIRECTION OUTPUT ;
    USE SIGNAL ;
    ANTENNADIFFAREA 0.702900 ;
    PORT
      LAYER met3 ;
        RECT 791.020 569.880 791.620 570.480 ;
    END
  END dout[127]
  PIN dout[12]
    DIRECTION OUTPUT ;
    USE SIGNAL ;
    ANTENNADIFFAREA 0.702900 ;
    PORT
      LAYER met3 ;
        RECT 791.020 318.280 791.620 318.880 ;
    END
  END dout[12]
  PIN dout[13]
    DIRECTION OUTPUT ;
    USE SIGNAL ;
    ANTENNADIFFAREA 0.702900 ;
    PORT
      LAYER met3 ;
        RECT 791.020 329.160 791.620 329.760 ;
    END
  END dout[13]
  PIN dout[14]
    DIRECTION OUTPUT ;
    USE SIGNAL ;
    ANTENNADIFFAREA 0.702900 ;
    PORT
      LAYER met3 ;
        RECT 791.020 251.640 791.620 252.240 ;
    END
  END dout[14]
  PIN dout[15]
    DIRECTION OUTPUT ;
    USE SIGNAL ;
    ANTENNADIFFAREA 0.702900 ;
    PORT
      LAYER met3 ;
        RECT 791.020 308.760 791.620 309.360 ;
    END
  END dout[15]
  PIN dout[16]
    DIRECTION OUTPUT ;
    USE SIGNAL ;
    ANTENNADIFFAREA 0.702900 ;
    PORT
      LAYER met3 ;
        RECT 791.020 334.600 791.620 335.200 ;
    END
  END dout[16]
  PIN dout[17]
    DIRECTION OUTPUT ;
    USE SIGNAL ;
    ANTENNADIFFAREA 0.702900 ;
    PORT
      LAYER met3 ;
        RECT 791.020 304.680 791.620 305.280 ;
    END
  END dout[17]
  PIN dout[18]
    DIRECTION OUTPUT ;
    USE SIGNAL ;
    ANTENNADIFFAREA 0.702900 ;
    PORT
      LAYER met3 ;
        RECT 791.020 322.360 791.620 322.960 ;
    END
  END dout[18]
  PIN dout[19]
    DIRECTION OUTPUT ;
    USE SIGNAL ;
    ANTENNADIFFAREA 0.702900 ;
    PORT
      LAYER met3 ;
        RECT 791.020 338.680 791.620 339.280 ;
    END
  END dout[19]
  PIN dout[1]
    DIRECTION OUTPUT ;
    USE SIGNAL ;
    ANTENNADIFFAREA 0.702900 ;
    PORT
      LAYER met2 ;
        RECT 403.970 0.000 404.250 0.280 ;
    END
  END dout[1]
  PIN dout[20]
    DIRECTION OUTPUT ;
    USE SIGNAL ;
    ANTENNADIFFAREA 0.702900 ;
    PORT
      LAYER met3 ;
        RECT 791.020 435.240 791.620 435.840 ;
    END
  END dout[20]
  PIN dout[21]
    DIRECTION OUTPUT ;
    USE SIGNAL ;
    ANTENNADIFFAREA 0.702900 ;
    PORT
      LAYER met3 ;
        RECT 791.020 331.880 791.620 332.480 ;
    END
  END dout[21]
  PIN dout[22]
    DIRECTION OUTPUT ;
    USE SIGNAL ;
    ANTENNADIFFAREA 0.702900 ;
    PORT
      LAYER met3 ;
        RECT 791.020 306.040 791.620 306.640 ;
    END
  END dout[22]
  PIN dout[23]
    DIRECTION OUTPUT ;
    USE SIGNAL ;
    ANTENNADIFFAREA 0.702900 ;
    PORT
      LAYER met3 ;
        RECT 791.020 349.560 791.620 350.160 ;
    END
  END dout[23]
  PIN dout[24]
    DIRECTION OUTPUT ;
    USE SIGNAL ;
    ANTENNADIFFAREA 0.702900 ;
    PORT
      LAYER met2 ;
        RECT 471.130 0.000 471.410 0.280 ;
    END
  END dout[24]
  PIN dout[25]
    DIRECTION OUTPUT ;
    USE SIGNAL ;
    ANTENNADIFFAREA 0.702900 ;
    PORT
      LAYER met2 ;
        RECT 464.690 0.000 464.970 0.280 ;
    END
  END dout[25]
  PIN dout[26]
    DIRECTION OUTPUT ;
    USE SIGNAL ;
    ANTENNADIFFAREA 0.702900 ;
    PORT
      LAYER met2 ;
        RECT 466.530 0.000 466.810 0.280 ;
    END
  END dout[26]
  PIN dout[27]
    DIRECTION OUTPUT ;
    USE SIGNAL ;
    ANTENNADIFFAREA 0.702900 ;
    PORT
      LAYER met2 ;
        RECT 477.570 0.000 477.850 0.280 ;
    END
  END dout[27]
  PIN dout[28]
    DIRECTION OUTPUT ;
    USE SIGNAL ;
    ANTENNADIFFAREA 0.702900 ;
    PORT
      LAYER met2 ;
        RECT 470.210 0.000 470.490 0.280 ;
    END
  END dout[28]
  PIN dout[29]
    DIRECTION OUTPUT ;
    USE SIGNAL ;
    ANTENNADIFFAREA 0.702900 ;
    PORT
      LAYER met2 ;
        RECT 454.570 0.000 454.850 0.280 ;
    END
  END dout[29]
  PIN dout[2]
    DIRECTION OUTPUT ;
    USE SIGNAL ;
    ANTENNADIFFAREA 0.702900 ;
    PORT
      LAYER met2 ;
        RECT 387.410 0.000 387.690 0.280 ;
    END
  END dout[2]
  PIN dout[30]
    DIRECTION OUTPUT ;
    USE SIGNAL ;
    ANTENNADIFFAREA 0.702900 ;
    PORT
      LAYER met2 ;
        RECT 456.410 0.000 456.690 0.280 ;
    END
  END dout[30]
  PIN dout[31]
    DIRECTION OUTPUT ;
    USE SIGNAL ;
    ANTENNADIFFAREA 0.702900 ;
    PORT
      LAYER met2 ;
        RECT 467.450 0.000 467.730 0.280 ;
    END
  END dout[31]
  PIN dout[32]
    DIRECTION OUTPUT ;
    USE SIGNAL ;
    ANTENNADIFFAREA 0.702900 ;
    PORT
      LAYER met2 ;
        RECT 395.690 802.060 395.970 802.340 ;
    END
  END dout[32]
  PIN dout[33]
    DIRECTION OUTPUT ;
    USE SIGNAL ;
    ANTENNADIFFAREA 0.702900 ;
    PORT
      LAYER met2 ;
        RECT 370.850 802.060 371.130 802.340 ;
    END
  END dout[33]
  PIN dout[34]
    DIRECTION OUTPUT ;
    USE SIGNAL ;
    ANTENNADIFFAREA 0.702900 ;
    PORT
      LAYER met2 ;
        RECT 388.330 802.060 388.610 802.340 ;
    END
  END dout[34]
  PIN dout[35]
    DIRECTION OUTPUT ;
    USE SIGNAL ;
    ANTENNADIFFAREA 0.702900 ;
    PORT
      LAYER met2 ;
        RECT 379.130 802.060 379.410 802.340 ;
    END
  END dout[35]
  PIN dout[36]
    DIRECTION OUTPUT ;
    USE SIGNAL ;
    ANTENNADIFFAREA 0.702900 ;
    PORT
      LAYER met2 ;
        RECT 354.290 802.060 354.570 802.340 ;
    END
  END dout[36]
  PIN dout[37]
    DIRECTION OUTPUT ;
    USE SIGNAL ;
    ANTENNADIFFAREA 0.702900 ;
    PORT
      LAYER met2 ;
        RECT 403.970 802.060 404.250 802.340 ;
    END
  END dout[37]
  PIN dout[38]
    DIRECTION OUTPUT ;
    USE SIGNAL ;
    ANTENNADIFFAREA 0.702900 ;
    PORT
      LAYER met2 ;
        RECT 401.210 802.060 401.490 802.340 ;
    END
  END dout[38]
  PIN dout[39]
    DIRECTION OUTPUT ;
    USE SIGNAL ;
    ANTENNADIFFAREA 0.702900 ;
    PORT
      LAYER met2 ;
        RECT 380.970 802.060 381.250 802.340 ;
    END
  END dout[39]
  PIN dout[3]
    DIRECTION OUTPUT ;
    USE SIGNAL ;
    ANTENNADIFFAREA 0.702900 ;
    PORT
      LAYER met2 ;
        RECT 364.410 802.060 364.690 802.340 ;
    END
  END dout[3]
  PIN dout[40]
    DIRECTION OUTPUT ;
    USE SIGNAL ;
    ANTENNADIFFAREA 0.702900 ;
    PORT
      LAYER met3 ;
        RECT 791.020 144.200 791.620 144.800 ;
    END
  END dout[40]
  PIN dout[41]
    DIRECTION OUTPUT ;
    USE SIGNAL ;
    ANTENNADIFFAREA 0.702900 ;
    PORT
      LAYER met2 ;
        RECT 620.170 0.000 620.450 0.280 ;
    END
  END dout[41]
  PIN dout[42]
    DIRECTION OUTPUT ;
    USE SIGNAL ;
    ANTENNADIFFAREA 0.702900 ;
    PORT
      LAYER met2 ;
        RECT 643.170 0.000 643.450 0.280 ;
    END
  END dout[42]
  PIN dout[43]
    DIRECTION OUTPUT ;
    USE SIGNAL ;
    ANTENNADIFFAREA 0.702900 ;
    PORT
      LAYER met2 ;
        RECT 645.010 0.000 645.290 0.280 ;
    END
  END dout[43]
  PIN dout[44]
    DIRECTION OUTPUT ;
    USE SIGNAL ;
    ANTENNADIFFAREA 0.702900 ;
    PORT
      LAYER met2 ;
        RECT 635.810 0.000 636.090 0.280 ;
    END
  END dout[44]
  PIN dout[45]
    DIRECTION OUTPUT ;
    USE SIGNAL ;
    ANTENNADIFFAREA 0.702900 ;
    PORT
      LAYER met2 ;
        RECT 648.690 0.000 648.970 0.280 ;
    END
  END dout[45]
  PIN dout[46]
    DIRECTION OUTPUT ;
    USE SIGNAL ;
    ANTENNADIFFAREA 0.702900 ;
    PORT
      LAYER met2 ;
        RECT 645.930 0.000 646.210 0.280 ;
    END
  END dout[46]
  PIN dout[47]
    DIRECTION OUTPUT ;
    USE SIGNAL ;
    ANTENNADIFFAREA 0.702900 ;
    PORT
      LAYER met2 ;
        RECT 642.250 0.000 642.530 0.280 ;
    END
  END dout[47]
  PIN dout[48]
    DIRECTION OUTPUT ;
    USE SIGNAL ;
    ANTENNADIFFAREA 0.702900 ;
    PORT
      LAYER met3 ;
        RECT 791.020 621.560 791.620 622.160 ;
    END
  END dout[48]
  PIN dout[49]
    DIRECTION OUTPUT ;
    USE SIGNAL ;
    ANTENNADIFFAREA 0.702900 ;
    PORT
      LAYER met3 ;
        RECT 791.020 610.680 791.620 611.280 ;
    END
  END dout[49]
  PIN dout[4]
    DIRECTION OUTPUT ;
    USE SIGNAL ;
    ANTENNADIFFAREA 0.702900 ;
    PORT
      LAYER met3 ;
        RECT 791.020 458.360 791.620 458.960 ;
    END
  END dout[4]
  PIN dout[50]
    DIRECTION OUTPUT ;
    USE SIGNAL ;
    ANTENNADIFFAREA 0.702900 ;
    PORT
      LAYER met3 ;
        RECT 791.020 595.720 791.620 596.320 ;
    END
  END dout[50]
  PIN dout[51]
    DIRECTION OUTPUT ;
    USE SIGNAL ;
    ANTENNADIFFAREA 0.702900 ;
    PORT
      LAYER met3 ;
        RECT 791.020 602.520 791.620 603.120 ;
    END
  END dout[51]
  PIN dout[52]
    DIRECTION OUTPUT ;
    USE SIGNAL ;
    ANTENNADIFFAREA 0.702900 ;
    PORT
      LAYER met3 ;
        RECT 791.020 631.080 791.620 631.680 ;
    END
  END dout[52]
  PIN dout[53]
    DIRECTION OUTPUT ;
    USE SIGNAL ;
    ANTENNADIFFAREA 0.702900 ;
    PORT
      LAYER met3 ;
        RECT 791.020 622.920 791.620 623.520 ;
    END
  END dout[53]
  PIN dout[54]
    DIRECTION OUTPUT ;
    USE SIGNAL ;
    ANTENNADIFFAREA 0.702900 ;
    PORT
      LAYER met3 ;
        RECT 791.020 632.440 791.620 633.040 ;
    END
  END dout[54]
  PIN dout[55]
    DIRECTION OUTPUT ;
    USE SIGNAL ;
    ANTENNADIFFAREA 0.702900 ;
    PORT
      LAYER met2 ;
        RECT 572.330 802.060 572.610 802.340 ;
    END
  END dout[55]
  PIN dout[56]
    DIRECTION OUTPUT ;
    USE SIGNAL ;
    ANTENNADIFFAREA 0.702900 ;
    PORT
      LAYER met3 ;
        RECT 791.020 138.760 791.620 139.360 ;
    END
  END dout[56]
  PIN dout[57]
    DIRECTION OUTPUT ;
    USE SIGNAL ;
    ANTENNADIFFAREA 0.702900 ;
    PORT
      LAYER met3 ;
        RECT 791.020 272.040 791.620 272.640 ;
    END
  END dout[57]
  PIN dout[58]
    DIRECTION OUTPUT ;
    USE SIGNAL ;
    ANTENNADIFFAREA 0.702900 ;
    PORT
      LAYER met3 ;
        RECT 791.020 250.280 791.620 250.880 ;
    END
  END dout[58]
  PIN dout[59]
    DIRECTION OUTPUT ;
    USE SIGNAL ;
    ANTENNADIFFAREA 0.702900 ;
    PORT
      LAYER met3 ;
        RECT 791.020 262.520 791.620 263.120 ;
    END
  END dout[59]
  PIN dout[5]
    DIRECTION OUTPUT ;
    USE SIGNAL ;
    ANTENNADIFFAREA 0.702900 ;
    PORT
      LAYER met2 ;
        RECT 439.850 0.000 440.130 0.280 ;
    END
  END dout[5]
  PIN dout[60]
    DIRECTION OUTPUT ;
    USE SIGNAL ;
    ANTENNADIFFAREA 0.702900 ;
    PORT
      LAYER met3 ;
        RECT 791.020 233.960 791.620 234.560 ;
    END
  END dout[60]
  PIN dout[61]
    DIRECTION OUTPUT ;
    USE SIGNAL ;
    ANTENNADIFFAREA 0.702900 ;
    PORT
      LAYER met3 ;
        RECT 791.020 242.120 791.620 242.720 ;
    END
  END dout[61]
  PIN dout[62]
    DIRECTION OUTPUT ;
    USE SIGNAL ;
    ANTENNADIFFAREA 0.702900 ;
    PORT
      LAYER met3 ;
        RECT 791.020 259.800 791.620 260.400 ;
    END
  END dout[62]
  PIN dout[63]
    DIRECTION OUTPUT ;
    USE SIGNAL ;
    ANTENNADIFFAREA 0.702900 ;
    PORT
      LAYER met3 ;
        RECT 791.020 236.680 791.620 237.280 ;
    END
  END dout[63]
  PIN dout[64]
    DIRECTION OUTPUT ;
    USE SIGNAL ;
    ANTENNADIFFAREA 0.702900 ;
    PORT
      LAYER met2 ;
        RECT 391.090 802.060 391.370 802.340 ;
    END
  END dout[64]
  PIN dout[65]
    DIRECTION OUTPUT ;
    USE SIGNAL ;
    ANTENNADIFFAREA 0.702900 ;
    PORT
      LAYER met2 ;
        RECT 383.730 802.060 384.010 802.340 ;
    END
  END dout[65]
  PIN dout[66]
    DIRECTION OUTPUT ;
    USE SIGNAL ;
    ANTENNADIFFAREA 0.702900 ;
    PORT
      LAYER met2 ;
        RECT 377.290 802.060 377.570 802.340 ;
    END
  END dout[66]
  PIN dout[67]
    DIRECTION OUTPUT ;
    USE SIGNAL ;
    ANTENNADIFFAREA 0.702900 ;
    PORT
      LAYER met2 ;
        RECT 387.410 802.060 387.690 802.340 ;
    END
  END dout[67]
  PIN dout[68]
    DIRECTION OUTPUT ;
    USE SIGNAL ;
    ANTENNADIFFAREA 0.702900 ;
    PORT
      LAYER met2 ;
        RECT 399.370 802.060 399.650 802.340 ;
    END
  END dout[68]
  PIN dout[69]
    DIRECTION OUTPUT ;
    USE SIGNAL ;
    ANTENNADIFFAREA 0.702900 ;
    PORT
      LAYER met2 ;
        RECT 356.130 802.060 356.410 802.340 ;
    END
  END dout[69]
  PIN dout[6]
    DIRECTION OUTPUT ;
    USE SIGNAL ;
    ANTENNADIFFAREA 0.702900 ;
    PORT
      LAYER met2 ;
        RECT 411.330 0.000 411.610 0.280 ;
    END
  END dout[6]
  PIN dout[70]
    DIRECTION OUTPUT ;
    USE SIGNAL ;
    ANTENNADIFFAREA 0.702900 ;
    PORT
      LAYER met2 ;
        RECT 378.210 802.060 378.490 802.340 ;
    END
  END dout[70]
  PIN dout[71]
    DIRECTION OUTPUT ;
    USE SIGNAL ;
    ANTENNADIFFAREA 0.702900 ;
    PORT
      LAYER met2 ;
        RECT 381.890 802.060 382.170 802.340 ;
    END
  END dout[71]
  PIN dout[72]
    DIRECTION OUTPUT ;
    USE SIGNAL ;
    ANTENNADIFFAREA 0.702900 ;
    PORT
      LAYER met2 ;
        RECT 485.850 0.000 486.130 0.280 ;
    END
  END dout[72]
  PIN dout[73]
    DIRECTION OUTPUT ;
    USE SIGNAL ;
    ANTENNADIFFAREA 0.702900 ;
    PORT
      LAYER met2 ;
        RECT 571.410 0.000 571.690 0.280 ;
    END
  END dout[73]
  PIN dout[74]
    DIRECTION OUTPUT ;
    USE SIGNAL ;
    ANTENNADIFFAREA 0.702900 ;
    PORT
      LAYER met2 ;
        RECT 496.890 0.000 497.170 0.280 ;
    END
  END dout[74]
  PIN dout[75]
    DIRECTION OUTPUT ;
    USE SIGNAL ;
    ANTENNADIFFAREA 0.702900 ;
    PORT
      LAYER met2 ;
        RECT 586.130 0.000 586.410 0.280 ;
    END
  END dout[75]
  PIN dout[76]
    DIRECTION OUTPUT ;
    USE SIGNAL ;
    ANTENNADIFFAREA 0.702900 ;
    PORT
      LAYER met2 ;
        RECT 486.770 0.000 487.050 0.280 ;
    END
  END dout[76]
  PIN dout[77]
    DIRECTION OUTPUT ;
    USE SIGNAL ;
    ANTENNADIFFAREA 0.702900 ;
    PORT
      LAYER met2 ;
        RECT 587.050 0.000 587.330 0.280 ;
    END
  END dout[77]
  PIN dout[78]
    DIRECTION OUTPUT ;
    USE SIGNAL ;
    ANTENNADIFFAREA 0.702900 ;
    PORT
      LAYER met2 ;
        RECT 593.490 0.000 593.770 0.280 ;
    END
  END dout[78]
  PIN dout[79]
    DIRECTION OUTPUT ;
    USE SIGNAL ;
    ANTENNADIFFAREA 0.702900 ;
    PORT
      LAYER met2 ;
        RECT 487.690 0.000 487.970 0.280 ;
    END
  END dout[79]
  PIN dout[7]
    DIRECTION OUTPUT ;
    USE SIGNAL ;
    ANTENNADIFFAREA 0.702900 ;
    PORT
      LAYER met2 ;
        RECT 440.770 0.000 441.050 0.280 ;
    END
  END dout[7]
  PIN dout[80]
    DIRECTION OUTPUT ;
    USE SIGNAL ;
    ANTENNADIFFAREA 0.702900 ;
    PORT
      LAYER met3 ;
        RECT 791.020 432.520 791.620 433.120 ;
    END
  END dout[80]
  PIN dout[81]
    DIRECTION OUTPUT ;
    USE SIGNAL ;
    ANTENNADIFFAREA 0.702900 ;
    PORT
      LAYER met3 ;
        RECT 791.020 412.120 791.620 412.720 ;
    END
  END dout[81]
  PIN dout[82]
    DIRECTION OUTPUT ;
    USE SIGNAL ;
    ANTENNADIFFAREA 0.702900 ;
    PORT
      LAYER met3 ;
        RECT 791.020 387.640 791.620 388.240 ;
    END
  END dout[82]
  PIN dout[83]
    DIRECTION OUTPUT ;
    USE SIGNAL ;
    ANTENNADIFFAREA 0.702900 ;
    PORT
      LAYER met3 ;
        RECT 791.020 397.160 791.620 397.760 ;
    END
  END dout[83]
  PIN dout[84]
    DIRECTION OUTPUT ;
    USE SIGNAL ;
    ANTENNADIFFAREA 0.702900 ;
    PORT
      LAYER met3 ;
        RECT 791.020 395.800 791.620 396.400 ;
    END
  END dout[84]
  PIN dout[85]
    DIRECTION OUTPUT ;
    USE SIGNAL ;
    ANTENNADIFFAREA 0.702900 ;
    PORT
      LAYER met3 ;
        RECT 791.020 389.000 791.620 389.600 ;
    END
  END dout[85]
  PIN dout[86]
    DIRECTION OUTPUT ;
    USE SIGNAL ;
    ANTENNADIFFAREA 0.702900 ;
    PORT
      LAYER met3 ;
        RECT 791.020 384.920 791.620 385.520 ;
    END
  END dout[86]
  PIN dout[87]
    DIRECTION OUTPUT ;
    USE SIGNAL ;
    ANTENNADIFFAREA 0.702900 ;
    PORT
      LAYER met2 ;
        RECT 580.610 802.060 580.890 802.340 ;
    END
  END dout[87]
  PIN dout[88]
    DIRECTION OUTPUT ;
    USE SIGNAL ;
    ANTENNADIFFAREA 0.702900 ;
    PORT
      LAYER met3 ;
        RECT 791.020 636.520 791.620 637.120 ;
    END
  END dout[88]
  PIN dout[89]
    DIRECTION OUTPUT ;
    USE SIGNAL ;
    ANTENNADIFFAREA 0.702900 ;
    PORT
      LAYER met2 ;
        RECT 734.250 802.060 734.530 802.340 ;
    END
  END dout[89]
  PIN dout[8]
    DIRECTION OUTPUT ;
    USE SIGNAL ;
    ANTENNADIFFAREA 0.702900 ;
    PORT
      LAYER met2 ;
        RECT 647.770 0.000 648.050 0.280 ;
    END
  END dout[8]
  PIN dout[90]
    DIRECTION OUTPUT ;
    USE SIGNAL ;
    ANTENNADIFFAREA 0.702900 ;
    PORT
      LAYER met2 ;
        RECT 645.010 802.060 645.290 802.340 ;
    END
  END dout[90]
  PIN dout[91]
    DIRECTION OUTPUT ;
    USE SIGNAL ;
    ANTENNADIFFAREA 0.702900 ;
    PORT
      LAYER met3 ;
        RECT 791.020 629.720 791.620 630.320 ;
    END
  END dout[91]
  PIN dout[92]
    DIRECTION OUTPUT ;
    USE SIGNAL ;
    ANTENNADIFFAREA 0.702900 ;
    PORT
      LAYER met2 ;
        RECT 745.290 802.060 745.570 802.340 ;
    END
  END dout[92]
  PIN dout[93]
    DIRECTION OUTPUT ;
    USE SIGNAL ;
    ANTENNADIFFAREA 0.702900 ;
    PORT
      LAYER met2 ;
        RECT 742.530 802.060 742.810 802.340 ;
    END
  END dout[93]
  PIN dout[94]
    DIRECTION OUTPUT ;
    USE SIGNAL ;
    ANTENNADIFFAREA 0.702900 ;
    PORT
      LAYER met3 ;
        RECT 791.020 640.600 791.620 641.200 ;
    END
  END dout[94]
  PIN dout[95]
    DIRECTION OUTPUT ;
    USE SIGNAL ;
    ANTENNADIFFAREA 0.702900 ;
    PORT
      LAYER met3 ;
        RECT 791.020 639.240 791.620 639.840 ;
    END
  END dout[95]
  PIN dout[96]
    DIRECTION OUTPUT ;
    USE SIGNAL ;
    ANTENNADIFFAREA 0.702900 ;
    PORT
      LAYER met2 ;
        RECT 520.810 802.060 521.090 802.340 ;
    END
  END dout[96]
  PIN dout[97]
    DIRECTION OUTPUT ;
    USE SIGNAL ;
    ANTENNADIFFAREA 0.702900 ;
    PORT
      LAYER met2 ;
        RECT 512.530 802.060 512.810 802.340 ;
    END
  END dout[97]
  PIN dout[98]
    DIRECTION OUTPUT ;
    USE SIGNAL ;
    ANTENNADIFFAREA 0.702900 ;
    PORT
      LAYER met2 ;
        RECT 506.090 802.060 506.370 802.340 ;
    END
  END dout[98]
  PIN dout[99]
    DIRECTION OUTPUT ;
    USE SIGNAL ;
    ANTENNADIFFAREA 0.702900 ;
    PORT
      LAYER met2 ;
        RECT 519.890 802.060 520.170 802.340 ;
    END
  END dout[99]
  PIN dout[9]
    DIRECTION OUTPUT ;
    USE SIGNAL ;
    ANTENNADIFFAREA 0.702900 ;
    PORT
      LAYER met2 ;
        RECT 607.290 0.000 607.570 0.280 ;
    END
  END dout[9]
  PIN key_in[0]
    DIRECTION INPUT ;
    USE SIGNAL ;
    ANTENNAGATEAREA 0.213000 ;
    PORT
      LAYER met2 ;
        RECT 105.890 0.000 106.170 0.280 ;
    END
  END key_in[0]
  PIN key_in[100]
    DIRECTION INPUT ;
    USE SIGNAL ;
    ANTENNAGATEAREA 0.213000 ;
    PORT
      LAYER met2 ;
        RECT 225.490 802.060 225.770 802.340 ;
    END
  END key_in[100]
  PIN key_in[101]
    DIRECTION INPUT ;
    USE SIGNAL ;
    ANTENNAGATEAREA 0.213000 ;
    PORT
      LAYER met3 ;
        RECT 0.000 520.920 0.600 521.520 ;
    END
  END key_in[101]
  PIN key_in[102]
    DIRECTION INPUT ;
    USE SIGNAL ;
    ANTENNAGATEAREA 0.213000 ;
    PORT
      LAYER met3 ;
        RECT 0.000 652.840 0.600 653.440 ;
    END
  END key_in[102]
  PIN key_in[103]
    DIRECTION INPUT ;
    USE SIGNAL ;
    ANTENNAGATEAREA 0.213000 ;
    PORT
      LAYER met2 ;
        RECT 156.490 802.060 156.770 802.340 ;
    END
  END key_in[103]
  PIN key_in[104]
    DIRECTION INPUT ;
    USE SIGNAL ;
    ANTENNAGATEAREA 0.213000 ;
    PORT
      LAYER met2 ;
        RECT 327.610 0.000 327.890 0.280 ;
    END
  END key_in[104]
  PIN key_in[105]
    DIRECTION INPUT ;
    USE SIGNAL ;
    ANTENNAGATEAREA 0.213000 ;
    PORT
      LAYER met3 ;
        RECT 0.000 418.920 0.600 419.520 ;
    END
  END key_in[105]
  PIN key_in[106]
    DIRECTION INPUT ;
    USE SIGNAL ;
    ANTENNAGATEAREA 0.213000 ;
    PORT
      LAYER met2 ;
        RECT 305.530 0.000 305.810 0.280 ;
    END
  END key_in[106]
  PIN key_in[107]
    DIRECTION INPUT ;
    USE SIGNAL ;
    ANTENNAGATEAREA 0.213000 ;
    PORT
      LAYER met2 ;
        RECT 356.130 0.000 356.410 0.280 ;
    END
  END key_in[107]
  PIN key_in[108]
    DIRECTION INPUT ;
    USE SIGNAL ;
    ANTENNAGATEAREA 0.213000 ;
    PORT
      LAYER met2 ;
        RECT 317.490 0.000 317.770 0.280 ;
    END
  END key_in[108]
  PIN key_in[109]
    DIRECTION INPUT ;
    USE SIGNAL ;
    ANTENNAGATEAREA 0.213000 ;
    PORT
      LAYER met2 ;
        RECT 277.930 0.000 278.210 0.280 ;
    END
  END key_in[109]
  PIN key_in[10]
    DIRECTION INPUT ;
    USE SIGNAL ;
    ANTENNAGATEAREA 0.213000 ;
    PORT
      LAYER met2 ;
        RECT 172.130 0.000 172.410 0.280 ;
    END
  END key_in[10]
  PIN key_in[110]
    DIRECTION INPUT ;
    USE SIGNAL ;
    ANTENNAGATEAREA 0.213000 ;
    PORT
      LAYER met2 ;
        RECT 233.770 0.000 234.050 0.280 ;
    END
  END key_in[110]
  PIN key_in[111]
    DIRECTION INPUT ;
    USE SIGNAL ;
    ANTENNAGATEAREA 0.213000 ;
    PORT
      LAYER met2 ;
        RECT 279.770 0.000 280.050 0.280 ;
    END
  END key_in[111]
  PIN key_in[112]
    DIRECTION INPUT ;
    USE SIGNAL ;
    ANTENNAGATEAREA 0.213000 ;
    PORT
      LAYER met2 ;
        RECT 155.570 802.060 155.850 802.340 ;
    END
  END key_in[112]
  PIN key_in[113]
    DIRECTION INPUT ;
    USE SIGNAL ;
    ANTENNAGATEAREA 0.213000 ;
    PORT
      LAYER met2 ;
        RECT 139.930 802.060 140.210 802.340 ;
    END
  END key_in[113]
  PIN key_in[114]
    DIRECTION INPUT ;
    USE SIGNAL ;
    ANTENNAGATEAREA 0.213000 ;
    PORT
      LAYER met2 ;
        RECT 204.330 802.060 204.610 802.340 ;
    END
  END key_in[114]
  PIN key_in[115]
    DIRECTION INPUT ;
    USE SIGNAL ;
    ANTENNAGATEAREA 0.213000 ;
    PORT
      LAYER met2 ;
        RECT 101.290 802.060 101.570 802.340 ;
    END
  END key_in[115]
  PIN key_in[116]
    DIRECTION INPUT ;
    USE SIGNAL ;
    ANTENNAGATEAREA 0.213000 ;
    PORT
      LAYER met3 ;
        RECT 0.000 712.680 0.600 713.280 ;
    END
  END key_in[116]
  PIN key_in[117]
    DIRECTION INPUT ;
    USE SIGNAL ;
    ANTENNAGATEAREA 0.213000 ;
    PORT
      LAYER met3 ;
        RECT 0.000 606.600 0.600 607.200 ;
    END
  END key_in[117]
  PIN key_in[118]
    DIRECTION INPUT ;
    USE SIGNAL ;
    ANTENNAGATEAREA 0.213000 ;
    PORT
      LAYER met3 ;
        RECT 0.000 544.040 0.600 544.640 ;
    END
  END key_in[118]
  PIN key_in[119]
    DIRECTION INPUT ;
    USE SIGNAL ;
    ANTENNAGATEAREA 0.213000 ;
    PORT
      LAYER met3 ;
        RECT 0.000 564.440 0.600 565.040 ;
    END
  END key_in[119]
  PIN key_in[11]
    DIRECTION INPUT ;
    USE SIGNAL ;
    ANTENNAGATEAREA 0.213000 ;
    PORT
      LAYER met3 ;
        RECT 0.000 251.640 0.600 252.240 ;
    END
  END key_in[11]
  PIN key_in[120]
    DIRECTION INPUT ;
    USE SIGNAL ;
    ANTENNAGATEAREA 0.213000 ;
    PORT
      LAYER met3 ;
        RECT 0.000 467.880 0.600 468.480 ;
    END
  END key_in[120]
  PIN key_in[121]
    DIRECTION INPUT ;
    USE SIGNAL ;
    ANTENNAGATEAREA 0.213000 ;
    PORT
      LAYER met2 ;
        RECT 183.170 802.060 183.450 802.340 ;
    END
  END key_in[121]
  PIN key_in[122]
    DIRECTION INPUT ;
    USE SIGNAL ;
    ANTENNAGATEAREA 0.213000 ;
    PORT
      LAYER met2 ;
        RECT 265.970 802.060 266.250 802.340 ;
    END
  END key_in[122]
  PIN key_in[123]
    DIRECTION INPUT ;
    USE SIGNAL ;
    ANTENNAGATEAREA 0.213000 ;
    PORT
      LAYER met2 ;
        RECT 317.490 802.060 317.770 802.340 ;
    END
  END key_in[123]
  PIN key_in[124]
    DIRECTION INPUT ;
    USE SIGNAL ;
    ANTENNAGATEAREA 0.213000 ;
    PORT
      LAYER met2 ;
        RECT 329.450 802.060 329.730 802.340 ;
    END
  END key_in[124]
  PIN key_in[125]
    DIRECTION INPUT ;
    USE SIGNAL ;
    ANTENNAGATEAREA 0.213000 ;
    PORT
      LAYER met3 ;
        RECT 0.000 572.600 0.600 573.200 ;
    END
  END key_in[125]
  PIN key_in[126]
    DIRECTION INPUT ;
    USE SIGNAL ;
    ANTENNAGATEAREA 0.213000 ;
    PORT
      LAYER met3 ;
        RECT 0.000 636.520 0.600 637.120 ;
    END
  END key_in[126]
  PIN key_in[127]
    DIRECTION INPUT ;
    USE SIGNAL ;
    ANTENNAGATEAREA 0.213000 ;
    PORT
      LAYER met2 ;
        RECT 195.130 802.060 195.410 802.340 ;
    END
  END key_in[127]
  PIN key_in[128]
    DIRECTION INPUT ;
    USE SIGNAL ;
    ANTENNAGATEAREA 0.213000 ;
    PORT
      LAYER met2 ;
        RECT 117.850 0.000 118.130 0.280 ;
    END
  END key_in[128]
  PIN key_in[129]
    DIRECTION INPUT ;
    USE SIGNAL ;
    ANTENNAGATEAREA 0.213000 ;
    PORT
      LAYER met2 ;
        RECT 90.250 0.000 90.530 0.280 ;
    END
  END key_in[129]
  PIN key_in[12]
    DIRECTION INPUT ;
    USE SIGNAL ;
    ANTENNAGATEAREA 0.213000 ;
    PORT
      LAYER met2 ;
        RECT 211.690 0.000 211.970 0.280 ;
    END
  END key_in[12]
  PIN key_in[130]
    DIRECTION INPUT ;
    USE SIGNAL ;
    ANTENNAGATEAREA 0.213000 ;
    PORT
      LAYER met2 ;
        RECT 162.010 0.000 162.290 0.280 ;
    END
  END key_in[130]
  PIN key_in[131]
    DIRECTION INPUT ;
    USE SIGNAL ;
    ANTENNAGATEAREA 0.213000 ;
    PORT
      LAYER met3 ;
        RECT 0.000 233.960 0.600 234.560 ;
    END
  END key_in[131]
  PIN key_in[132]
    DIRECTION INPUT ;
    USE SIGNAL ;
    ANTENNAGATEAREA 0.213000 ;
    PORT
      LAYER met3 ;
        RECT 0.000 227.160 0.600 227.760 ;
    END
  END key_in[132]
  PIN key_in[133]
    DIRECTION INPUT ;
    USE SIGNAL ;
    ANTENNAGATEAREA 0.213000 ;
    PORT
      LAYER met3 ;
        RECT 0.000 431.160 0.600 431.760 ;
    END
  END key_in[133]
  PIN key_in[134]
    DIRECTION INPUT ;
    USE SIGNAL ;
    ANTENNAGATEAREA 0.213000 ;
    PORT
      LAYER met3 ;
        RECT 0.000 280.200 0.600 280.800 ;
    END
  END key_in[134]
  PIN key_in[135]
    DIRECTION INPUT ;
    USE SIGNAL ;
    ANTENNAGATEAREA 0.213000 ;
    PORT
      LAYER met3 ;
        RECT 0.000 326.440 0.600 327.040 ;
    END
  END key_in[135]
  PIN key_in[136]
    DIRECTION INPUT ;
    USE SIGNAL ;
    ANTENNAGATEAREA 0.213000 ;
    PORT
      LAYER met3 ;
        RECT 0.000 137.400 0.600 138.000 ;
    END
  END key_in[136]
  PIN key_in[137]
    DIRECTION INPUT ;
    USE SIGNAL ;
    ANTENNAGATEAREA 0.213000 ;
    PORT
      LAYER met3 ;
        RECT 0.000 282.920 0.600 283.520 ;
    END
  END key_in[137]
  PIN key_in[138]
    DIRECTION INPUT ;
    USE SIGNAL ;
    ANTENNAGATEAREA 0.213000 ;
    PORT
      LAYER met3 ;
        RECT 0.000 126.520 0.600 127.120 ;
    END
  END key_in[138]
  PIN key_in[139]
    DIRECTION INPUT ;
    USE SIGNAL ;
    ANTENNAGATEAREA 0.213000 ;
    PORT
      LAYER met3 ;
        RECT 0.000 242.120 0.600 242.720 ;
    END
  END key_in[139]
  PIN key_in[13]
    DIRECTION INPUT ;
    USE SIGNAL ;
    ANTENNAGATEAREA 0.213000 ;
    PORT
      LAYER met3 ;
        RECT 0.000 269.320 0.600 269.920 ;
    END
  END key_in[13]
  PIN key_in[140]
    DIRECTION INPUT ;
    USE SIGNAL ;
    ANTENNAGATEAREA 0.213000 ;
    PORT
      LAYER met2 ;
        RECT 212.610 0.000 212.890 0.280 ;
    END
  END key_in[140]
  PIN key_in[141]
    DIRECTION INPUT ;
    USE SIGNAL ;
    ANTENNAGATEAREA 0.213000 ;
    PORT
      LAYER met3 ;
        RECT 0.000 308.760 0.600 309.360 ;
    END
  END key_in[141]
  PIN key_in[142]
    DIRECTION INPUT ;
    USE SIGNAL ;
    ANTENNAGATEAREA 0.213000 ;
    PORT
      LAYER met3 ;
        RECT 0.000 189.080 0.600 189.680 ;
    END
  END key_in[142]
  PIN key_in[143]
    DIRECTION INPUT ;
    USE SIGNAL ;
    ANTENNAGATEAREA 0.213000 ;
    PORT
      LAYER met2 ;
        RECT 248.490 0.000 248.770 0.280 ;
    END
  END key_in[143]
  PIN key_in[144]
    DIRECTION INPUT ;
    USE SIGNAL ;
    ANTENNAGATEAREA 0.213000 ;
    PORT
      LAYER met3 ;
        RECT 0.000 386.280 0.600 386.880 ;
    END
  END key_in[144]
  PIN key_in[145]
    DIRECTION INPUT ;
    USE SIGNAL ;
    ANTENNAGATEAREA 0.213000 ;
    PORT
      LAYER met3 ;
        RECT 0.000 318.280 0.600 318.880 ;
    END
  END key_in[145]
  PIN key_in[146]
    DIRECTION INPUT ;
    USE SIGNAL ;
    ANTENNAGATEAREA 0.213000 ;
    PORT
      LAYER met3 ;
        RECT 0.000 383.560 0.600 384.160 ;
    END
  END key_in[146]
  PIN key_in[147]
    DIRECTION INPUT ;
    USE SIGNAL ;
    ANTENNAGATEAREA 0.213000 ;
    PORT
      LAYER met3 ;
        RECT 0.000 306.040 0.600 306.640 ;
    END
  END key_in[147]
  PIN key_in[148]
    DIRECTION INPUT ;
    USE SIGNAL ;
    ANTENNAGATEAREA 0.213000 ;
    PORT
      LAYER met3 ;
        RECT 0.000 365.880 0.600 366.480 ;
    END
  END key_in[148]
  PIN key_in[149]
    DIRECTION INPUT ;
    USE SIGNAL ;
    ANTENNAGATEAREA 0.213000 ;
    PORT
      LAYER met3 ;
        RECT 0.000 314.200 0.600 314.800 ;
    END
  END key_in[149]
  PIN key_in[14]
    DIRECTION INPUT ;
    USE SIGNAL ;
    ANTENNAGATEAREA 0.213000 ;
    PORT
      LAYER met3 ;
        RECT 0.000 149.640 0.600 150.240 ;
    END
  END key_in[14]
  PIN key_in[150]
    DIRECTION INPUT ;
    USE SIGNAL ;
    ANTENNAGATEAREA 0.213000 ;
    PORT
      LAYER met3 ;
        RECT 0.000 374.040 0.600 374.640 ;
    END
  END key_in[150]
  PIN key_in[151]
    DIRECTION INPUT ;
    USE SIGNAL ;
    ANTENNAGATEAREA 0.213000 ;
    PORT
      LAYER met3 ;
        RECT 0.000 423.000 0.600 423.600 ;
    END
  END key_in[151]
  PIN key_in[152]
    DIRECTION INPUT ;
    USE SIGNAL ;
    ANTENNAGATEAREA 0.213000 ;
    PORT
      LAYER met3 ;
        RECT 0.000 140.120 0.600 140.720 ;
    END
  END key_in[152]
  PIN key_in[153]
    DIRECTION INPUT ;
    USE SIGNAL ;
    ANTENNAGATEAREA 0.213000 ;
    PORT
      LAYER met2 ;
        RECT 132.570 0.000 132.850 0.280 ;
    END
  END key_in[153]
  PIN key_in[154]
    DIRECTION INPUT ;
    USE SIGNAL ;
    ANTENNAGATEAREA 0.213000 ;
    PORT
      LAYER met3 ;
        RECT 0.000 191.800 0.600 192.400 ;
    END
  END key_in[154]
  PIN key_in[155]
    DIRECTION INPUT ;
    USE SIGNAL ;
    ANTENNAGATEAREA 0.213000 ;
    PORT
      LAYER met3 ;
        RECT 0.000 209.480 0.600 210.080 ;
    END
  END key_in[155]
  PIN key_in[156]
    DIRECTION INPUT ;
    USE SIGNAL ;
    ANTENNAGATEAREA 0.213000 ;
    PORT
      LAYER met3 ;
        RECT 0.000 212.200 0.600 212.800 ;
    END
  END key_in[156]
  PIN key_in[157]
    DIRECTION INPUT ;
    USE SIGNAL ;
    ANTENNAGATEAREA 0.213000 ;
    PORT
      LAYER met3 ;
        RECT 0.000 262.520 0.600 263.120 ;
    END
  END key_in[157]
  PIN key_in[158]
    DIRECTION INPUT ;
    USE SIGNAL ;
    ANTENNAGATEAREA 0.213000 ;
    PORT
      LAYER met3 ;
        RECT 0.000 277.480 0.600 278.080 ;
    END
  END key_in[158]
  PIN key_in[159]
    DIRECTION INPUT ;
    USE SIGNAL ;
    ANTENNAGATEAREA 0.213000 ;
    PORT
      LAYER met2 ;
        RECT 216.290 0.000 216.570 0.280 ;
    END
  END key_in[159]
  PIN key_in[15]
    DIRECTION INPUT ;
    USE SIGNAL ;
    ANTENNAGATEAREA 0.213000 ;
    PORT
      LAYER met2 ;
        RECT 218.130 0.000 218.410 0.280 ;
    END
  END key_in[15]
  PIN key_in[160]
    DIRECTION INPUT ;
    USE SIGNAL ;
    ANTENNAGATEAREA 0.213000 ;
    PORT
      LAYER met3 ;
        RECT 0.000 485.560 0.600 486.160 ;
    END
  END key_in[160]
  PIN key_in[161]
    DIRECTION INPUT ;
    USE SIGNAL ;
    ANTENNAGATEAREA 0.213000 ;
    PORT
      LAYER met3 ;
        RECT 0.000 527.720 0.600 528.320 ;
    END
  END key_in[161]
  PIN key_in[162]
    DIRECTION INPUT ;
    USE SIGNAL ;
    ANTENNAGATEAREA 0.213000 ;
    PORT
      LAYER met2 ;
        RECT 325.770 802.060 326.050 802.340 ;
    END
  END key_in[162]
  PIN key_in[163]
    DIRECTION INPUT ;
    USE SIGNAL ;
    ANTENNAGATEAREA 0.213000 ;
    PORT
      LAYER met3 ;
        RECT 0.000 480.120 0.600 480.720 ;
    END
  END key_in[163]
  PIN key_in[164]
    DIRECTION INPUT ;
    USE SIGNAL ;
    ANTENNAGATEAREA 0.213000 ;
    PORT
      LAYER met3 ;
        RECT 0.000 454.280 0.600 454.880 ;
    END
  END key_in[164]
  PIN key_in[165]
    DIRECTION INPUT ;
    USE SIGNAL ;
    ANTENNAGATEAREA 0.213000 ;
    PORT
      LAYER met3 ;
        RECT 0.000 503.240 0.600 503.840 ;
    END
  END key_in[165]
  PIN key_in[166]
    DIRECTION INPUT ;
    USE SIGNAL ;
    ANTENNAGATEAREA 0.213000 ;
    PORT
      LAYER met2 ;
        RECT 173.970 802.060 174.250 802.340 ;
    END
  END key_in[166]
  PIN key_in[167]
    DIRECTION INPUT ;
    USE SIGNAL ;
    ANTENNAGATEAREA 0.213000 ;
    PORT
      LAYER met2 ;
        RECT 241.130 802.060 241.410 802.340 ;
    END
  END key_in[167]
  PIN key_in[168]
    DIRECTION INPUT ;
    USE SIGNAL ;
    ANTENNAGATEAREA 0.213000 ;
    PORT
      LAYER met2 ;
        RECT 243.890 0.000 244.170 0.280 ;
    END
  END key_in[168]
  PIN key_in[169]
    DIRECTION INPUT ;
    USE SIGNAL ;
    ANTENNAGATEAREA 0.213000 ;
    PORT
      LAYER met2 ;
        RECT 359.810 0.000 360.090 0.280 ;
    END
  END key_in[169]
  PIN key_in[16]
    DIRECTION INPUT ;
    USE SIGNAL ;
    ANTENNAGATEAREA 0.213000 ;
    PORT
      LAYER met3 ;
        RECT 0.000 393.080 0.600 393.680 ;
    END
  END key_in[16]
  PIN key_in[170]
    DIRECTION INPUT ;
    USE SIGNAL ;
    ANTENNAGATEAREA 0.213000 ;
    PORT
      LAYER met2 ;
        RECT 285.290 0.000 285.570 0.280 ;
    END
  END key_in[170]
  PIN key_in[171]
    DIRECTION INPUT ;
    USE SIGNAL ;
    ANTENNAGATEAREA 0.213000 ;
    PORT
      LAYER met3 ;
        RECT 0.000 376.760 0.600 377.360 ;
    END
  END key_in[171]
  PIN key_in[172]
    DIRECTION INPUT ;
    USE SIGNAL ;
    ANTENNAGATEAREA 0.213000 ;
    PORT
      LAYER met2 ;
        RECT 329.450 0.000 329.730 0.280 ;
    END
  END key_in[172]
  PIN key_in[173]
    DIRECTION INPUT ;
    USE SIGNAL ;
    ANTENNAGATEAREA 0.213000 ;
    PORT
      LAYER met3 ;
        RECT 0.000 444.760 0.600 445.360 ;
    END
  END key_in[173]
  PIN key_in[174]
    DIRECTION INPUT ;
    USE SIGNAL ;
    ANTENNAGATEAREA 0.213000 ;
    PORT
      LAYER met2 ;
        RECT 275.170 0.000 275.450 0.280 ;
    END
  END key_in[174]
  PIN key_in[175]
    DIRECTION INPUT ;
    USE SIGNAL ;
    ANTENNAGATEAREA 0.213000 ;
    PORT
      LAYER met2 ;
        RECT 360.730 0.000 361.010 0.280 ;
    END
  END key_in[175]
  PIN key_in[176]
    DIRECTION INPUT ;
    USE SIGNAL ;
    ANTENNAGATEAREA 0.213000 ;
    PORT
      LAYER met2 ;
        RECT 258.610 802.060 258.890 802.340 ;
    END
  END key_in[176]
  PIN key_in[177]
    DIRECTION INPUT ;
    USE SIGNAL ;
    ANTENNAGATEAREA 0.213000 ;
    PORT
      LAYER met3 ;
        RECT 0.000 446.120 0.600 446.720 ;
    END
  END key_in[177]
  PIN key_in[178]
    DIRECTION INPUT ;
    USE SIGNAL ;
    ANTENNAGATEAREA 0.213000 ;
    PORT
      LAYER met3 ;
        RECT 0.000 409.400 0.600 410.000 ;
    END
  END key_in[178]
  PIN key_in[179]
    DIRECTION INPUT ;
    USE SIGNAL ;
    ANTENNAGATEAREA 0.213000 ;
    PORT
      LAYER met3 ;
        RECT 0.000 496.440 0.600 497.040 ;
    END
  END key_in[179]
  PIN key_in[17]
    DIRECTION INPUT ;
    USE SIGNAL ;
    ANTENNAGATEAREA 0.213000 ;
    PORT
      LAYER met3 ;
        RECT 0.000 321.000 0.600 321.600 ;
    END
  END key_in[17]
  PIN key_in[180]
    DIRECTION INPUT ;
    USE SIGNAL ;
    ANTENNAGATEAREA 0.213000 ;
    PORT
      LAYER met3 ;
        RECT 0.000 432.520 0.600 433.120 ;
    END
  END key_in[180]
  PIN key_in[181]
    DIRECTION INPUT ;
    USE SIGNAL ;
    ANTENNAGATEAREA 0.213000 ;
    PORT
      LAYER met3 ;
        RECT 0.000 455.640 0.600 456.240 ;
    END
  END key_in[181]
  PIN key_in[182]
    DIRECTION INPUT ;
    USE SIGNAL ;
    ANTENNAGATEAREA 0.213000 ;
    PORT
      LAYER met3 ;
        RECT 0.000 458.360 0.600 458.960 ;
    END
  END key_in[182]
  PIN key_in[183]
    DIRECTION INPUT ;
    USE SIGNAL ;
    ANTENNAGATEAREA 0.213000 ;
    PORT
      LAYER met2 ;
        RECT 199.730 802.060 200.010 802.340 ;
    END
  END key_in[183]
  PIN key_in[184]
    DIRECTION INPUT ;
    USE SIGNAL ;
    ANTENNAGATEAREA 0.213000 ;
    PORT
      LAYER met2 ;
        RECT 286.210 0.000 286.490 0.280 ;
    END
  END key_in[184]
  PIN key_in[185]
    DIRECTION INPUT ;
    USE SIGNAL ;
    ANTENNAGATEAREA 0.213000 ;
    PORT
      LAYER met2 ;
        RECT 256.770 0.000 257.050 0.280 ;
    END
  END key_in[185]
  PIN key_in[186]
    DIRECTION INPUT ;
    USE SIGNAL ;
    ANTENNAGATEAREA 0.213000 ;
    PORT
      LAYER met3 ;
        RECT 0.000 371.320 0.600 371.920 ;
    END
  END key_in[186]
  PIN key_in[187]
    DIRECTION INPUT ;
    USE SIGNAL ;
    ANTENNAGATEAREA 0.213000 ;
    PORT
      LAYER met2 ;
        RECT 260.450 802.060 260.730 802.340 ;
    END
  END key_in[187]
  PIN key_in[188]
    DIRECTION INPUT ;
    USE SIGNAL ;
    ANTENNAGATEAREA 0.213000 ;
    PORT
      LAYER met2 ;
        RECT 362.570 0.000 362.850 0.280 ;
    END
  END key_in[188]
  PIN key_in[189]
    DIRECTION INPUT ;
    USE SIGNAL ;
    ANTENNAGATEAREA 0.213000 ;
    PORT
      LAYER met3 ;
        RECT 0.000 352.280 0.600 352.880 ;
    END
  END key_in[189]
  PIN key_in[18]
    DIRECTION INPUT ;
    USE SIGNAL ;
    ANTENNAGATEAREA 0.213000 ;
    PORT
      LAYER met3 ;
        RECT 0.000 395.800 0.600 396.400 ;
    END
  END key_in[18]
  PIN key_in[190]
    DIRECTION INPUT ;
    USE SIGNAL ;
    ANTENNAGATEAREA 0.213000 ;
    PORT
      LAYER met3 ;
        RECT 0.000 501.880 0.600 502.480 ;
    END
  END key_in[190]
  PIN key_in[191]
    DIRECTION INPUT ;
    USE SIGNAL ;
    ANTENNAGATEAREA 0.213000 ;
    PORT
      LAYER met2 ;
        RECT 314.730 0.000 315.010 0.280 ;
    END
  END key_in[191]
  PIN key_in[192]
    DIRECTION INPUT ;
    USE SIGNAL ;
    ANTENNAGATEAREA 0.213000 ;
    PORT
      LAYER met2 ;
        RECT 163.850 802.060 164.130 802.340 ;
    END
  END key_in[192]
  PIN key_in[193]
    DIRECTION INPUT ;
    USE SIGNAL ;
    ANTENNAGATEAREA 0.213000 ;
    PORT
      LAYER met3 ;
        RECT 0.000 599.800 0.600 600.400 ;
    END
  END key_in[193]
  PIN key_in[194]
    DIRECTION INPUT ;
    USE SIGNAL ;
    ANTENNAGATEAREA 0.213000 ;
    PORT
      LAYER met2 ;
        RECT 290.810 802.060 291.090 802.340 ;
    END
  END key_in[194]
  PIN key_in[195]
    DIRECTION INPUT ;
    USE SIGNAL ;
    ANTENNAGATEAREA 0.213000 ;
    PORT
      LAYER met3 ;
        RECT 0.000 662.360 0.600 662.960 ;
    END
  END key_in[195]
  PIN key_in[196]
    DIRECTION INPUT ;
    USE SIGNAL ;
    ANTENNAGATEAREA 0.213000 ;
    PORT
      LAYER met2 ;
        RECT 288.970 802.060 289.250 802.340 ;
    END
  END key_in[196]
  PIN key_in[197]
    DIRECTION INPUT ;
    USE SIGNAL ;
    ANTENNAGATEAREA 0.213000 ;
    PORT
      LAYER met3 ;
        RECT 0.000 625.640 0.600 626.240 ;
    END
  END key_in[197]
  PIN key_in[198]
    DIRECTION INPUT ;
    USE SIGNAL ;
    ANTENNAGATEAREA 0.213000 ;
    PORT
      LAYER met2 ;
        RECT 214.450 802.060 214.730 802.340 ;
    END
  END key_in[198]
  PIN key_in[199]
    DIRECTION INPUT ;
    USE SIGNAL ;
    ANTENNAGATEAREA 0.213000 ;
    PORT
      LAYER met2 ;
        RECT 254.930 802.060 255.210 802.340 ;
    END
  END key_in[199]
  PIN key_in[19]
    DIRECTION INPUT ;
    USE SIGNAL ;
    ANTENNAGATEAREA 0.213000 ;
    PORT
      LAYER met3 ;
        RECT 0.000 272.040 0.600 272.640 ;
    END
  END key_in[19]
  PIN key_in[1]
    DIRECTION INPUT ;
    USE SIGNAL ;
    ANTENNAGATEAREA 0.213000 ;
    PORT
      LAYER met2 ;
        RECT 94.850 0.000 95.130 0.280 ;
    END
  END key_in[1]
  PIN key_in[200]
    DIRECTION INPUT ;
    USE SIGNAL ;
    ANTENNAGATEAREA 0.213000 ;
    PORT
      LAYER met2 ;
        RECT 322.090 0.000 322.370 0.280 ;
    END
  END key_in[200]
  PIN key_in[201]
    DIRECTION INPUT ;
    USE SIGNAL ;
    ANTENNAGATEAREA 0.213000 ;
    PORT
      LAYER met2 ;
        RECT 366.250 0.000 366.530 0.280 ;
    END
  END key_in[201]
  PIN key_in[202]
    DIRECTION INPUT ;
    USE SIGNAL ;
    ANTENNAGATEAREA 0.213000 ;
    PORT
      LAYER met2 ;
        RECT 278.850 0.000 279.130 0.280 ;
    END
  END key_in[202]
  PIN key_in[203]
    DIRECTION INPUT ;
    USE SIGNAL ;
    ANTENNAGATEAREA 0.213000 ;
    PORT
      LAYER met3 ;
        RECT 0.000 360.440 0.600 361.040 ;
    END
  END key_in[203]
  PIN key_in[204]
    DIRECTION INPUT ;
    USE SIGNAL ;
    ANTENNAGATEAREA 0.213000 ;
    PORT
      LAYER met2 ;
        RECT 338.650 0.000 338.930 0.280 ;
    END
  END key_in[204]
  PIN key_in[205]
    DIRECTION INPUT ;
    USE SIGNAL ;
    ANTENNAGATEAREA 0.213000 ;
    PORT
      LAYER met2 ;
        RECT 273.330 0.000 273.610 0.280 ;
    END
  END key_in[205]
  PIN key_in[206]
    DIRECTION INPUT ;
    USE SIGNAL ;
    ANTENNAGATEAREA 0.213000 ;
    PORT
      LAYER met2 ;
        RECT 369.010 0.000 369.290 0.280 ;
    END
  END key_in[206]
  PIN key_in[207]
    DIRECTION INPUT ;
    USE SIGNAL ;
    ANTENNAGATEAREA 0.213000 ;
    PORT
      LAYER met2 ;
        RECT 323.930 0.000 324.210 0.280 ;
    END
  END key_in[207]
  PIN key_in[208]
    DIRECTION INPUT ;
    USE SIGNAL ;
    ANTENNAGATEAREA 0.213000 ;
    PORT
      LAYER met2 ;
        RECT 289.890 802.060 290.170 802.340 ;
    END
  END key_in[208]
  PIN key_in[209]
    DIRECTION INPUT ;
    USE SIGNAL ;
    ANTENNAGATEAREA 0.213000 ;
    PORT
      LAYER met2 ;
        RECT 254.010 802.060 254.290 802.340 ;
    END
  END key_in[209]
  PIN key_in[20]
    DIRECTION INPUT ;
    USE SIGNAL ;
    ANTENNAGATEAREA 0.213000 ;
    PORT
      LAYER met3 ;
        RECT 0.000 375.400 0.600 376.000 ;
    END
  END key_in[20]
  PIN key_in[210]
    DIRECTION INPUT ;
    USE SIGNAL ;
    ANTENNAGATEAREA 0.213000 ;
    PORT
      LAYER met2 ;
        RECT 291.730 802.060 292.010 802.340 ;
    END
  END key_in[210]
  PIN key_in[211]
    DIRECTION INPUT ;
    USE SIGNAL ;
    ANTENNAGATEAREA 0.213000 ;
    PORT
      LAYER met2 ;
        RECT 205.250 802.060 205.530 802.340 ;
    END
  END key_in[211]
  PIN key_in[212]
    DIRECTION INPUT ;
    USE SIGNAL ;
    ANTENNAGATEAREA 0.213000 ;
    PORT
      LAYER met2 ;
        RECT 369.010 802.060 369.290 802.340 ;
    END
  END key_in[212]
  PIN key_in[213]
    DIRECTION INPUT ;
    USE SIGNAL ;
    ANTENNAGATEAREA 0.213000 ;
    PORT
      LAYER met3 ;
        RECT 0.000 569.880 0.600 570.480 ;
    END
  END key_in[213]
  PIN key_in[214]
    DIRECTION INPUT ;
    USE SIGNAL ;
    ANTENNAGATEAREA 0.213000 ;
    PORT
      LAYER met3 ;
        RECT 0.000 535.880 0.600 536.480 ;
    END
  END key_in[214]
  PIN key_in[215]
    DIRECTION INPUT ;
    USE SIGNAL ;
    ANTENNAGATEAREA 0.213000 ;
    PORT
      LAYER met2 ;
        RECT 164.770 802.060 165.050 802.340 ;
    END
  END key_in[215]
  PIN key_in[216]
    DIRECTION INPUT ;
    USE SIGNAL ;
    ANTENNAGATEAREA 0.213000 ;
    PORT
      LAYER met2 ;
        RECT 303.690 802.060 303.970 802.340 ;
    END
  END key_in[216]
  PIN key_in[217]
    DIRECTION INPUT ;
    USE SIGNAL ;
    ANTENNAGATEAREA 0.213000 ;
    PORT
      LAYER met2 ;
        RECT 293.570 802.060 293.850 802.340 ;
    END
  END key_in[217]
  PIN key_in[218]
    DIRECTION INPUT ;
    USE SIGNAL ;
    ANTENNAGATEAREA 0.213000 ;
    PORT
      LAYER met3 ;
        RECT 0.000 427.080 0.600 427.680 ;
    END
  END key_in[218]
  PIN key_in[219]
    DIRECTION INPUT ;
    USE SIGNAL ;
    ANTENNAGATEAREA 0.213000 ;
    PORT
      LAYER met2 ;
        RECT 283.450 802.060 283.730 802.340 ;
    END
  END key_in[219]
  PIN key_in[21]
    DIRECTION INPUT ;
    USE SIGNAL ;
    ANTENNAGATEAREA 0.213000 ;
    PORT
      LAYER met3 ;
        RECT 0.000 319.640 0.600 320.240 ;
    END
  END key_in[21]
  PIN key_in[220]
    DIRECTION INPUT ;
    USE SIGNAL ;
    ANTENNAGATEAREA 0.213000 ;
    PORT
      LAYER met3 ;
        RECT 0.000 348.200 0.600 348.800 ;
    END
  END key_in[220]
  PIN key_in[221]
    DIRECTION INPUT ;
    USE SIGNAL ;
    ANTENNAGATEAREA 0.213000 ;
    PORT
      LAYER met2 ;
        RECT 318.410 802.060 318.690 802.340 ;
    END
  END key_in[221]
  PIN key_in[222]
    DIRECTION INPUT ;
    USE SIGNAL ;
    ANTENNAGATEAREA 0.213000 ;
    PORT
      LAYER met2 ;
        RECT 242.970 802.060 243.250 802.340 ;
    END
  END key_in[222]
  PIN key_in[223]
    DIRECTION INPUT ;
    USE SIGNAL ;
    ANTENNAGATEAREA 0.213000 ;
    PORT
      LAYER met2 ;
        RECT 367.170 0.000 367.450 0.280 ;
    END
  END key_in[223]
  PIN key_in[224]
    DIRECTION INPUT ;
    USE SIGNAL ;
    ANTENNAGATEAREA 0.213000 ;
    PORT
      LAYER met3 ;
        RECT 0.000 684.120 0.600 684.720 ;
    END
  END key_in[224]
  PIN key_in[225]
    DIRECTION INPUT ;
    USE SIGNAL ;
    ANTENNAGATEAREA 0.213000 ;
    PORT
      LAYER met3 ;
        RECT 0.000 552.200 0.600 552.800 ;
    END
  END key_in[225]
  PIN key_in[226]
    DIRECTION INPUT ;
    USE SIGNAL ;
    ANTENNAGATEAREA 0.213000 ;
    PORT
      LAYER met3 ;
        RECT 0.000 677.320 0.600 677.920 ;
    END
  END key_in[226]
  PIN key_in[227]
    DIRECTION INPUT ;
    USE SIGNAL ;
    ANTENNAGATEAREA 0.213000 ;
    PORT
      LAYER met3 ;
        RECT 0.000 620.200 0.600 620.800 ;
    END
  END key_in[227]
  PIN key_in[228]
    DIRECTION INPUT ;
    USE SIGNAL ;
    ANTENNAGATEAREA 0.213000 ;
    PORT
      LAYER met2 ;
        RECT 227.330 802.060 227.610 802.340 ;
    END
  END key_in[228]
  PIN key_in[229]
    DIRECTION INPUT ;
    USE SIGNAL ;
    ANTENNAGATEAREA 0.213000 ;
    PORT
      LAYER met3 ;
        RECT 0.000 515.480 0.600 516.080 ;
    END
  END key_in[229]
  PIN key_in[22]
    DIRECTION INPUT ;
    USE SIGNAL ;
    ANTENNAGATEAREA 0.213000 ;
    PORT
      LAYER met3 ;
        RECT 0.000 355.000 0.600 355.600 ;
    END
  END key_in[22]
  PIN key_in[230]
    DIRECTION INPUT ;
    USE SIGNAL ;
    ANTENNAGATEAREA 0.213000 ;
    PORT
      LAYER met3 ;
        RECT 0.000 658.280 0.600 658.880 ;
    END
  END key_in[230]
  PIN key_in[231]
    DIRECTION INPUT ;
    USE SIGNAL ;
    ANTENNAGATEAREA 0.213000 ;
    PORT
      LAYER met2 ;
        RECT 153.730 802.060 154.010 802.340 ;
    END
  END key_in[231]
  PIN key_in[232]
    DIRECTION INPUT ;
    USE SIGNAL ;
    ANTENNAGATEAREA 0.213000 ;
    PORT
      LAYER met2 ;
        RECT 330.370 0.000 330.650 0.280 ;
    END
  END key_in[232]
  PIN key_in[233]
    DIRECTION INPUT ;
    USE SIGNAL ;
    ANTENNAGATEAREA 0.213000 ;
    PORT
      LAYER met3 ;
        RECT 0.000 414.840 0.600 415.440 ;
    END
  END key_in[233]
  PIN key_in[234]
    DIRECTION INPUT ;
    USE SIGNAL ;
    ANTENNAGATEAREA 0.213000 ;
    PORT
      LAYER met2 ;
        RECT 308.290 0.000 308.570 0.280 ;
    END
  END key_in[234]
  PIN key_in[235]
    DIRECTION INPUT ;
    USE SIGNAL ;
    ANTENNAGATEAREA 0.213000 ;
    PORT
      LAYER met2 ;
        RECT 357.050 0.000 357.330 0.280 ;
    END
  END key_in[235]
  PIN key_in[236]
    DIRECTION INPUT ;
    USE SIGNAL ;
    ANTENNAGATEAREA 0.213000 ;
    PORT
      LAYER met2 ;
        RECT 318.410 0.000 318.690 0.280 ;
    END
  END key_in[236]
  PIN key_in[237]
    DIRECTION INPUT ;
    USE SIGNAL ;
    ANTENNAGATEAREA 0.213000 ;
    PORT
      LAYER met2 ;
        RECT 281.610 0.000 281.890 0.280 ;
    END
  END key_in[237]
  PIN key_in[238]
    DIRECTION INPUT ;
    USE SIGNAL ;
    ANTENNAGATEAREA 0.213000 ;
    PORT
      LAYER met2 ;
        RECT 238.370 0.000 238.650 0.280 ;
    END
  END key_in[238]
  PIN key_in[239]
    DIRECTION INPUT ;
    USE SIGNAL ;
    ANTENNAGATEAREA 0.213000 ;
    PORT
      LAYER met2 ;
        RECT 282.530 0.000 282.810 0.280 ;
    END
  END key_in[239]
  PIN key_in[23]
    DIRECTION INPUT ;
    USE SIGNAL ;
    ANTENNAGATEAREA 0.213000 ;
    PORT
      LAYER met3 ;
        RECT 0.000 428.440 0.600 429.040 ;
    END
  END key_in[23]
  PIN key_in[240]
    DIRECTION INPUT ;
    USE SIGNAL ;
    ANTENNAGATEAREA 0.213000 ;
    PORT
      LAYER met2 ;
        RECT 157.410 802.060 157.690 802.340 ;
    END
  END key_in[240]
  PIN key_in[241]
    DIRECTION INPUT ;
    USE SIGNAL ;
    ANTENNAGATEAREA 0.213000 ;
    PORT
      LAYER met2 ;
        RECT 144.530 802.060 144.810 802.340 ;
    END
  END key_in[241]
  PIN key_in[242]
    DIRECTION INPUT ;
    USE SIGNAL ;
    ANTENNAGATEAREA 0.213000 ;
    PORT
      LAYER met2 ;
        RECT 203.410 802.060 203.690 802.340 ;
    END
  END key_in[242]
  PIN key_in[243]
    DIRECTION INPUT ;
    USE SIGNAL ;
    ANTENNAGATEAREA 0.213000 ;
    PORT
      LAYER met2 ;
        RECT 105.890 802.060 106.170 802.340 ;
    END
  END key_in[243]
  PIN key_in[244]
    DIRECTION INPUT ;
    USE SIGNAL ;
    ANTENNAGATEAREA 0.213000 ;
    PORT
      LAYER met3 ;
        RECT 0.000 711.320 0.600 711.920 ;
    END
  END key_in[244]
  PIN key_in[245]
    DIRECTION INPUT ;
    USE SIGNAL ;
    ANTENNAGATEAREA 0.213000 ;
    PORT
      LAYER met3 ;
        RECT 0.000 607.960 0.600 608.560 ;
    END
  END key_in[245]
  PIN key_in[246]
    DIRECTION INPUT ;
    USE SIGNAL ;
    ANTENNAGATEAREA 0.213000 ;
    PORT
      LAYER met3 ;
        RECT 0.000 548.120 0.600 548.720 ;
    END
  END key_in[246]
  PIN key_in[247]
    DIRECTION INPUT ;
    USE SIGNAL ;
    ANTENNAGATEAREA 0.213000 ;
    PORT
      LAYER met3 ;
        RECT 0.000 567.160 0.600 567.760 ;
    END
  END key_in[247]
  PIN key_in[248]
    DIRECTION INPUT ;
    USE SIGNAL ;
    ANTENNAGATEAREA 0.213000 ;
    PORT
      LAYER met3 ;
        RECT 0.000 465.160 0.600 465.760 ;
    END
  END key_in[248]
  PIN key_in[249]
    DIRECTION INPUT ;
    USE SIGNAL ;
    ANTENNAGATEAREA 0.213000 ;
    PORT
      LAYER met2 ;
        RECT 186.850 802.060 187.130 802.340 ;
    END
  END key_in[249]
  PIN key_in[24]
    DIRECTION INPUT ;
    USE SIGNAL ;
    ANTENNAGATEAREA 0.213000 ;
    PORT
      LAYER met3 ;
        RECT 0.000 170.040 0.600 170.640 ;
    END
  END key_in[24]
  PIN key_in[250]
    DIRECTION INPUT ;
    USE SIGNAL ;
    ANTENNAGATEAREA 0.213000 ;
    PORT
      LAYER met2 ;
        RECT 265.050 802.060 265.330 802.340 ;
    END
  END key_in[250]
  PIN key_in[251]
    DIRECTION INPUT ;
    USE SIGNAL ;
    ANTENNAGATEAREA 0.213000 ;
    PORT
      LAYER met2 ;
        RECT 313.810 802.060 314.090 802.340 ;
    END
  END key_in[251]
  PIN key_in[252]
    DIRECTION INPUT ;
    USE SIGNAL ;
    ANTENNAGATEAREA 0.213000 ;
    PORT
      LAYER met2 ;
        RECT 326.690 802.060 326.970 802.340 ;
    END
  END key_in[252]
  PIN key_in[253]
    DIRECTION INPUT ;
    USE SIGNAL ;
    ANTENNAGATEAREA 0.213000 ;
    PORT
      LAYER met3 ;
        RECT 0.000 568.520 0.600 569.120 ;
    END
  END key_in[253]
  PIN key_in[254]
    DIRECTION INPUT ;
    USE SIGNAL ;
    ANTENNAGATEAREA 0.213000 ;
    PORT
      LAYER met3 ;
        RECT 0.000 631.080 0.600 631.680 ;
    END
  END key_in[254]
  PIN key_in[255]
    DIRECTION INPUT ;
    USE SIGNAL ;
    ANTENNAGATEAREA 0.213000 ;
    PORT
      LAYER met2 ;
        RECT 198.810 802.060 199.090 802.340 ;
    END
  END key_in[255]
  PIN key_in[25]
    DIRECTION INPUT ;
    USE SIGNAL ;
    ANTENNAGATEAREA 0.213000 ;
    PORT
      LAYER met2 ;
        RECT 140.850 0.000 141.130 0.280 ;
    END
  END key_in[25]
  PIN key_in[26]
    DIRECTION INPUT ;
    USE SIGNAL ;
    ANTENNAGATEAREA 0.213000 ;
    PORT
      LAYER met3 ;
        RECT 0.000 201.320 0.600 201.920 ;
    END
  END key_in[26]
  PIN key_in[27]
    DIRECTION INPUT ;
    USE SIGNAL ;
    ANTENNAGATEAREA 0.213000 ;
    PORT
      LAYER met3 ;
        RECT 0.000 187.720 0.600 188.320 ;
    END
  END key_in[27]
  PIN key_in[28]
    DIRECTION INPUT ;
    USE SIGNAL ;
    ANTENNAGATEAREA 0.213000 ;
    PORT
      LAYER met3 ;
        RECT 0.000 186.360 0.600 186.960 ;
    END
  END key_in[28]
  PIN key_in[29]
    DIRECTION INPUT ;
    USE SIGNAL ;
    ANTENNAGATEAREA 0.213000 ;
    PORT
      LAYER met3 ;
        RECT 0.000 238.040 0.600 238.640 ;
    END
  END key_in[29]
  PIN key_in[2]
    DIRECTION INPUT ;
    USE SIGNAL ;
    ANTENNAGATEAREA 0.213000 ;
    PORT
      LAYER met3 ;
        RECT 0.000 125.160 0.600 125.760 ;
    END
  END key_in[2]
  PIN key_in[30]
    DIRECTION INPUT ;
    USE SIGNAL ;
    ANTENNAGATEAREA 0.213000 ;
    PORT
      LAYER met3 ;
        RECT 0.000 270.680 0.600 271.280 ;
    END
  END key_in[30]
  PIN key_in[31]
    DIRECTION INPUT ;
    USE SIGNAL ;
    ANTENNAGATEAREA 0.213000 ;
    PORT
      LAYER met3 ;
        RECT 0.000 178.200 0.600 178.800 ;
    END
  END key_in[31]
  PIN key_in[32]
    DIRECTION INPUT ;
    USE SIGNAL ;
    ANTENNAGATEAREA 0.213000 ;
    PORT
      LAYER met3 ;
        RECT 0.000 500.520 0.600 501.120 ;
    END
  END key_in[32]
  PIN key_in[33]
    DIRECTION INPUT ;
    USE SIGNAL ;
    ANTENNAGATEAREA 0.213000 ;
    PORT
      LAYER met2 ;
        RECT 162.930 802.060 163.210 802.340 ;
    END
  END key_in[33]
  PIN key_in[34]
    DIRECTION INPUT ;
    USE SIGNAL ;
    ANTENNAGATEAREA 0.213000 ;
    PORT
      LAYER met2 ;
        RECT 292.650 802.060 292.930 802.340 ;
    END
  END key_in[34]
  PIN key_in[35]
    DIRECTION INPUT ;
    USE SIGNAL ;
    ANTENNAGATEAREA 0.213000 ;
    PORT
      LAYER met3 ;
        RECT 0.000 478.760 0.600 479.360 ;
    END
  END key_in[35]
  PIN key_in[36]
    DIRECTION INPUT ;
    USE SIGNAL ;
    ANTENNAGATEAREA 0.213000 ;
    PORT
      LAYER met3 ;
        RECT 0.000 425.720 0.600 426.320 ;
    END
  END key_in[36]
  PIN key_in[37]
    DIRECTION INPUT ;
    USE SIGNAL ;
    ANTENNAGATEAREA 0.213000 ;
    PORT
      LAYER met3 ;
        RECT 0.000 471.960 0.600 472.560 ;
    END
  END key_in[37]
  PIN key_in[38]
    DIRECTION INPUT ;
    USE SIGNAL ;
    ANTENNAGATEAREA 0.213000 ;
    PORT
      LAYER met3 ;
        RECT 0.000 635.160 0.600 635.760 ;
    END
  END key_in[38]
  PIN key_in[39]
    DIRECTION INPUT ;
    USE SIGNAL ;
    ANTENNAGATEAREA 0.213000 ;
    PORT
      LAYER met2 ;
        RECT 210.770 802.060 211.050 802.340 ;
    END
  END key_in[39]
  PIN key_in[3]
    DIRECTION INPUT ;
    USE SIGNAL ;
    ANTENNAGATEAREA 0.213000 ;
    PORT
      LAYER met3 ;
        RECT 0.000 236.680 0.600 237.280 ;
    END
  END key_in[3]
  PIN key_in[40]
    DIRECTION INPUT ;
    USE SIGNAL ;
    ANTENNAGATEAREA 0.213000 ;
    PORT
      LAYER met2 ;
        RECT 236.530 0.000 236.810 0.280 ;
    END
  END key_in[40]
  PIN key_in[41]
    DIRECTION INPUT ;
    USE SIGNAL ;
    ANTENNAGATEAREA 0.213000 ;
    PORT
      LAYER met2 ;
        RECT 358.890 0.000 359.170 0.280 ;
    END
  END key_in[41]
  PIN key_in[42]
    DIRECTION INPUT ;
    USE SIGNAL ;
    ANTENNAGATEAREA 0.213000 ;
    PORT
      LAYER met2 ;
        RECT 245.730 0.000 246.010 0.280 ;
    END
  END key_in[42]
  PIN key_in[43]
    DIRECTION INPUT ;
    USE SIGNAL ;
    ANTENNAGATEAREA 0.213000 ;
    PORT
      LAYER met3 ;
        RECT 0.000 390.360 0.600 390.960 ;
    END
  END key_in[43]
  PIN key_in[44]
    DIRECTION INPUT ;
    USE SIGNAL ;
    ANTENNAGATEAREA 0.213000 ;
    PORT
      LAYER met2 ;
        RECT 297.250 0.000 297.530 0.280 ;
    END
  END key_in[44]
  PIN key_in[45]
    DIRECTION INPUT ;
    USE SIGNAL ;
    ANTENNAGATEAREA 0.213000 ;
    PORT
      LAYER met3 ;
        RECT 0.000 469.240 0.600 469.840 ;
    END
  END key_in[45]
  PIN key_in[46]
    DIRECTION INPUT ;
    USE SIGNAL ;
    ANTENNAGATEAREA 0.213000 ;
    PORT
      LAYER met2 ;
        RECT 260.450 0.000 260.730 0.280 ;
    END
  END key_in[46]
  PIN key_in[47]
    DIRECTION INPUT ;
    USE SIGNAL ;
    ANTENNAGATEAREA 0.213000 ;
    PORT
      LAYER met2 ;
        RECT 361.650 0.000 361.930 0.280 ;
    END
  END key_in[47]
  PIN key_in[48]
    DIRECTION INPUT ;
    USE SIGNAL ;
    ANTENNAGATEAREA 0.213000 ;
    PORT
      LAYER met2 ;
        RECT 248.490 802.060 248.770 802.340 ;
    END
  END key_in[48]
  PIN key_in[49]
    DIRECTION INPUT ;
    USE SIGNAL ;
    ANTENNAGATEAREA 0.213000 ;
    PORT
      LAYER met3 ;
        RECT 0.000 439.320 0.600 439.920 ;
    END
  END key_in[49]
  PIN key_in[4]
    DIRECTION INPUT ;
    USE SIGNAL ;
    ANTENNAGATEAREA 0.213000 ;
    PORT
      LAYER met3 ;
        RECT 0.000 255.720 0.600 256.320 ;
    END
  END key_in[4]
  PIN key_in[50]
    DIRECTION INPUT ;
    USE SIGNAL ;
    ANTENNAGATEAREA 0.213000 ;
    PORT
      LAYER met3 ;
        RECT 0.000 405.320 0.600 405.920 ;
    END
  END key_in[50]
  PIN key_in[51]
    DIRECTION INPUT ;
    USE SIGNAL ;
    ANTENNAGATEAREA 0.213000 ;
    PORT
      LAYER met3 ;
        RECT 0.000 510.040 0.600 510.640 ;
    END
  END key_in[51]
  PIN key_in[52]
    DIRECTION INPUT ;
    USE SIGNAL ;
    ANTENNAGATEAREA 0.213000 ;
    PORT
      LAYER met3 ;
        RECT 0.000 424.360 0.600 424.960 ;
    END
  END key_in[52]
  PIN key_in[53]
    DIRECTION INPUT ;
    USE SIGNAL ;
    ANTENNAGATEAREA 0.213000 ;
    PORT
      LAYER met3 ;
        RECT 0.000 457.000 0.600 457.600 ;
    END
  END key_in[53]
  PIN key_in[54]
    DIRECTION INPUT ;
    USE SIGNAL ;
    ANTENNAGATEAREA 0.213000 ;
    PORT
      LAYER met3 ;
        RECT 0.000 470.600 0.600 471.200 ;
    END
  END key_in[54]
  PIN key_in[55]
    DIRECTION INPUT ;
    USE SIGNAL ;
    ANTENNAGATEAREA 0.213000 ;
    PORT
      LAYER met2 ;
        RECT 185.930 802.060 186.210 802.340 ;
    END
  END key_in[55]
  PIN key_in[56]
    DIRECTION INPUT ;
    USE SIGNAL ;
    ANTENNAGATEAREA 0.213000 ;
    PORT
      LAYER met2 ;
        RECT 261.370 0.000 261.650 0.280 ;
    END
  END key_in[56]
  PIN key_in[57]
    DIRECTION INPUT ;
    USE SIGNAL ;
    ANTENNAGATEAREA 0.213000 ;
    PORT
      LAYER met2 ;
        RECT 250.330 0.000 250.610 0.280 ;
    END
  END key_in[57]
  PIN key_in[58]
    DIRECTION INPUT ;
    USE SIGNAL ;
    ANTENNAGATEAREA 0.213000 ;
    PORT
      LAYER met3 ;
        RECT 0.000 353.640 0.600 354.240 ;
    END
  END key_in[58]
  PIN key_in[59]
    DIRECTION INPUT ;
    USE SIGNAL ;
    ANTENNAGATEAREA 0.213000 ;
    PORT
      LAYER met3 ;
        RECT 0.000 505.960 0.600 506.560 ;
    END
  END key_in[59]
  PIN key_in[5]
    DIRECTION INPUT ;
    USE SIGNAL ;
    ANTENNAGATEAREA 0.213000 ;
    PORT
      LAYER met3 ;
        RECT 0.000 433.880 0.600 434.480 ;
    END
  END key_in[5]
  PIN key_in[60]
    DIRECTION INPUT ;
    USE SIGNAL ;
    ANTENNAGATEAREA 0.213000 ;
    PORT
      LAYER met2 ;
        RECT 365.330 0.000 365.610 0.280 ;
    END
  END key_in[60]
  PIN key_in[61]
    DIRECTION INPUT ;
    USE SIGNAL ;
    ANTENNAGATEAREA 0.213000 ;
    PORT
      LAYER met3 ;
        RECT 0.000 333.240 0.600 333.840 ;
    END
  END key_in[61]
  PIN key_in[62]
    DIRECTION INPUT ;
    USE SIGNAL ;
    ANTENNAGATEAREA 0.213000 ;
    PORT
      LAYER met3 ;
        RECT 0.000 488.280 0.600 488.880 ;
    END
  END key_in[62]
  PIN key_in[63]
    DIRECTION INPUT ;
    USE SIGNAL ;
    ANTENNAGATEAREA 0.213000 ;
    PORT
      LAYER met2 ;
        RECT 296.330 0.000 296.610 0.280 ;
    END
  END key_in[63]
  PIN key_in[64]
    DIRECTION INPUT ;
    USE SIGNAL ;
    ANTENNAGATEAREA 0.213000 ;
    PORT
      LAYER met2 ;
        RECT 184.090 802.060 184.370 802.340 ;
    END
  END key_in[64]
  PIN key_in[65]
    DIRECTION INPUT ;
    USE SIGNAL ;
    ANTENNAGATEAREA 0.213000 ;
    PORT
      LAYER met3 ;
        RECT 0.000 576.680 0.600 577.280 ;
    END
  END key_in[65]
  PIN key_in[66]
    DIRECTION INPUT ;
    USE SIGNAL ;
    ANTENNAGATEAREA 0.213000 ;
    PORT
      LAYER met2 ;
        RECT 288.050 802.060 288.330 802.340 ;
    END
  END key_in[66]
  PIN key_in[67]
    DIRECTION INPUT ;
    USE SIGNAL ;
    ANTENNAGATEAREA 0.213000 ;
    PORT
      LAYER met3 ;
        RECT 0.000 663.720 0.600 664.320 ;
    END
  END key_in[67]
  PIN key_in[68]
    DIRECTION INPUT ;
    USE SIGNAL ;
    ANTENNAGATEAREA 0.213000 ;
    PORT
      LAYER met2 ;
        RECT 255.850 802.060 256.130 802.340 ;
    END
  END key_in[68]
  PIN key_in[69]
    DIRECTION INPUT ;
    USE SIGNAL ;
    ANTENNAGATEAREA 0.213000 ;
    PORT
      LAYER met3 ;
        RECT 0.000 594.360 0.600 594.960 ;
    END
  END key_in[69]
  PIN key_in[6]
    DIRECTION INPUT ;
    USE SIGNAL ;
    ANTENNAGATEAREA 0.213000 ;
    PORT
      LAYER met3 ;
        RECT 0.000 278.840 0.600 279.440 ;
    END
  END key_in[6]
  PIN key_in[70]
    DIRECTION INPUT ;
    USE SIGNAL ;
    ANTENNAGATEAREA 0.213000 ;
    PORT
      LAYER met2 ;
        RECT 211.690 802.060 211.970 802.340 ;
    END
  END key_in[70]
  PIN key_in[71]
    DIRECTION INPUT ;
    USE SIGNAL ;
    ANTENNAGATEAREA 0.213000 ;
    PORT
      LAYER met2 ;
        RECT 259.530 802.060 259.810 802.340 ;
    END
  END key_in[71]
  PIN key_in[72]
    DIRECTION INPUT ;
    USE SIGNAL ;
    ANTENNAGATEAREA 0.213000 ;
    PORT
      LAYER met2 ;
        RECT 323.010 0.000 323.290 0.280 ;
    END
  END key_in[72]
  PIN key_in[73]
    DIRECTION INPUT ;
    USE SIGNAL ;
    ANTENNAGATEAREA 0.213000 ;
    PORT
      LAYER met2 ;
        RECT 364.410 0.000 364.690 0.280 ;
    END
  END key_in[73]
  PIN key_in[74]
    DIRECTION INPUT ;
    USE SIGNAL ;
    ANTENNAGATEAREA 0.213000 ;
    PORT
      LAYER met2 ;
        RECT 264.130 0.000 264.410 0.280 ;
    END
  END key_in[74]
  PIN key_in[75]
    DIRECTION INPUT ;
    USE SIGNAL ;
    ANTENNAGATEAREA 0.213000 ;
    PORT
      LAYER met3 ;
        RECT 0.000 401.240 0.600 401.840 ;
    END
  END key_in[75]
  PIN key_in[76]
    DIRECTION INPUT ;
    USE SIGNAL ;
    ANTENNAGATEAREA 0.213000 ;
    PORT
      LAYER met2 ;
        RECT 336.810 0.000 337.090 0.280 ;
    END
  END key_in[76]
  PIN key_in[77]
    DIRECTION INPUT ;
    USE SIGNAL ;
    ANTENNAGATEAREA 0.213000 ;
    PORT
      LAYER met3 ;
        RECT 0.000 346.840 0.600 347.440 ;
    END
  END key_in[77]
  PIN key_in[78]
    DIRECTION INPUT ;
    USE SIGNAL ;
    ANTENNAGATEAREA 0.213000 ;
    PORT
      LAYER met2 ;
        RECT 368.090 0.000 368.370 0.280 ;
    END
  END key_in[78]
  PIN key_in[79]
    DIRECTION INPUT ;
    USE SIGNAL ;
    ANTENNAGATEAREA 0.213000 ;
    PORT
      LAYER met2 ;
        RECT 307.370 0.000 307.650 0.280 ;
    END
  END key_in[79]
  PIN key_in[7]
    DIRECTION INPUT ;
    USE SIGNAL ;
    ANTENNAGATEAREA 0.213000 ;
    PORT
      LAYER met3 ;
        RECT 0.000 357.720 0.600 358.320 ;
    END
  END key_in[7]
  PIN key_in[80]
    DIRECTION INPUT ;
    USE SIGNAL ;
    ANTENNAGATEAREA 0.213000 ;
    PORT
      LAYER met2 ;
        RECT 253.090 802.060 253.370 802.340 ;
    END
  END key_in[80]
  PIN key_in[81]
    DIRECTION INPUT ;
    USE SIGNAL ;
    ANTENNAGATEAREA 0.213000 ;
    PORT
      LAYER met2 ;
        RECT 243.890 802.060 244.170 802.340 ;
    END
  END key_in[81]
  PIN key_in[82]
    DIRECTION INPUT ;
    USE SIGNAL ;
    ANTENNAGATEAREA 0.213000 ;
    PORT
      LAYER met2 ;
        RECT 304.610 802.060 304.890 802.340 ;
    END
  END key_in[82]
  PIN key_in[83]
    DIRECTION INPUT ;
    USE SIGNAL ;
    ANTENNAGATEAREA 0.213000 ;
    PORT
      LAYER met2 ;
        RECT 216.290 802.060 216.570 802.340 ;
    END
  END key_in[83]
  PIN key_in[84]
    DIRECTION INPUT ;
    USE SIGNAL ;
    ANTENNAGATEAREA 0.213000 ;
    PORT
      LAYER met2 ;
        RECT 338.650 802.060 338.930 802.340 ;
    END
  END key_in[84]
  PIN key_in[85]
    DIRECTION INPUT ;
    USE SIGNAL ;
    ANTENNAGATEAREA 0.213000 ;
    PORT
      LAYER met3 ;
        RECT 0.000 588.920 0.600 589.520 ;
    END
  END key_in[85]
  PIN key_in[86]
    DIRECTION INPUT ;
    USE SIGNAL ;
    ANTENNAGATEAREA 0.213000 ;
    PORT
      LAYER met3 ;
        RECT 0.000 499.160 0.600 499.760 ;
    END
  END key_in[86]
  PIN key_in[87]
    DIRECTION INPUT ;
    USE SIGNAL ;
    ANTENNAGATEAREA 0.213000 ;
    PORT
      LAYER met3 ;
        RECT 0.000 624.280 0.600 624.880 ;
    END
  END key_in[87]
  PIN key_in[88]
    DIRECTION INPUT ;
    USE SIGNAL ;
    ANTENNAGATEAREA 0.213000 ;
    PORT
      LAYER met2 ;
        RECT 295.410 802.060 295.690 802.340 ;
    END
  END key_in[88]
  PIN key_in[89]
    DIRECTION INPUT ;
    USE SIGNAL ;
    ANTENNAGATEAREA 0.213000 ;
    PORT
      LAYER met2 ;
        RECT 286.210 802.060 286.490 802.340 ;
    END
  END key_in[89]
  PIN key_in[8]
    DIRECTION INPUT ;
    USE SIGNAL ;
    ANTENNAGATEAREA 0.213000 ;
    PORT
      LAYER met3 ;
        RECT 0.000 136.040 0.600 136.640 ;
    END
  END key_in[8]
  PIN key_in[90]
    DIRECTION INPUT ;
    USE SIGNAL ;
    ANTENNAGATEAREA 0.213000 ;
    PORT
      LAYER met3 ;
        RECT 0.000 435.240 0.600 435.840 ;
    END
  END key_in[90]
  PIN key_in[91]
    DIRECTION INPUT ;
    USE SIGNAL ;
    ANTENNAGATEAREA 0.213000 ;
    PORT
      LAYER met2 ;
        RECT 273.330 802.060 273.610 802.340 ;
    END
  END key_in[91]
  PIN key_in[92]
    DIRECTION INPUT ;
    USE SIGNAL ;
    ANTENNAGATEAREA 0.213000 ;
    PORT
      LAYER met2 ;
        RECT 321.170 0.000 321.450 0.280 ;
    END
  END key_in[92]
  PIN key_in[93]
    DIRECTION INPUT ;
    USE SIGNAL ;
    ANTENNAGATEAREA 0.213000 ;
    PORT
      LAYER met2 ;
        RECT 309.210 802.060 309.490 802.340 ;
    END
  END key_in[93]
  PIN key_in[94]
    DIRECTION INPUT ;
    USE SIGNAL ;
    ANTENNAGATEAREA 0.213000 ;
    PORT
      LAYER met2 ;
        RECT 226.410 802.060 226.690 802.340 ;
    END
  END key_in[94]
  PIN key_in[95]
    DIRECTION INPUT ;
    USE SIGNAL ;
    ANTENNAGATEAREA 0.213000 ;
    PORT
      LAYER met2 ;
        RECT 363.490 0.000 363.770 0.280 ;
    END
  END key_in[95]
  PIN key_in[96]
    DIRECTION INPUT ;
    USE SIGNAL ;
    ANTENNAGATEAREA 0.213000 ;
    PORT
      LAYER met3 ;
        RECT 0.000 688.200 0.600 688.800 ;
    END
  END key_in[96]
  PIN key_in[97]
    DIRECTION INPUT ;
    USE SIGNAL ;
    ANTENNAGATEAREA 0.213000 ;
    PORT
      LAYER met3 ;
        RECT 0.000 556.280 0.600 556.880 ;
    END
  END key_in[97]
  PIN key_in[98]
    DIRECTION INPUT ;
    USE SIGNAL ;
    ANTENNAGATEAREA 0.213000 ;
    PORT
      LAYER met3 ;
        RECT 0.000 675.960 0.600 676.560 ;
    END
  END key_in[98]
  PIN key_in[99]
    DIRECTION INPUT ;
    USE SIGNAL ;
    ANTENNAGATEAREA 0.213000 ;
    PORT
      LAYER met3 ;
        RECT 0.000 621.560 0.600 622.160 ;
    END
  END key_in[99]
  PIN key_in[9]
    DIRECTION INPUT ;
    USE SIGNAL ;
    ANTENNAGATEAREA 0.213000 ;
    PORT
      LAYER met3 ;
        RECT 0.000 310.120 0.600 310.720 ;
    END
  END key_in[9]
  PIN key_load
    DIRECTION INPUT ;
    USE SIGNAL ;
    ANTENNAGATEAREA 0.213000 ;
    PORT
      LAYER met2 ;
        RECT 383.730 0.000 384.010 0.280 ;
    END
  END key_load
  PIN key_ready
    DIRECTION OUTPUT ;
    USE SIGNAL ;
    ANTENNADIFFAREA 0.702900 ;
    PORT
      LAYER met2 ;
        RECT 381.890 0.000 382.170 0.280 ;
    END
  END key_ready
  PIN mode
    DIRECTION INPUT ;
    USE SIGNAL ;
    ANTENNAGATEAREA 0.213000 ;
    PORT
      LAYER met3 ;
        RECT 791.020 36.760 791.620 37.360 ;
    END
  END mode
  PIN ready
    DIRECTION OUTPUT ;
    USE SIGNAL ;
    ANTENNADIFFAREA 0.702900 ;
    PORT
      LAYER met2 ;
        RECT 382.810 0.000 383.090 0.280 ;
    END
  END ready
  PIN reset_n
    DIRECTION INPUT ;
    USE SIGNAL ;
    ANTENNAGATEAREA 0.159000 ;
    PORT
      LAYER met3 ;
        RECT 791.020 96.600 791.620 97.200 ;
    END
  END reset_n
  PIN start
    DIRECTION INPUT ;
    USE SIGNAL ;
    ANTENNAGATEAREA 0.213000 ;
    PORT
      LAYER met2 ;
        RECT 384.650 0.000 384.930 0.280 ;
    END
  END start
  OBS
      LAYER nwell ;
        RECT 5.330 10.795 785.870 788.885 ;
      LAYER li1 ;
        RECT 5.520 10.795 785.680 788.885 ;
      LAYER met1 ;
        RECT 0.990 3.780 790.670 797.600 ;
      LAYER met2 ;
        RECT 0.550 801.780 101.010 802.270 ;
        RECT 101.850 801.780 105.610 802.270 ;
        RECT 106.450 801.780 139.650 802.270 ;
        RECT 140.490 801.780 144.250 802.270 ;
        RECT 145.090 801.780 153.450 802.270 ;
        RECT 154.290 801.780 155.290 802.270 ;
        RECT 156.130 801.780 156.210 802.270 ;
        RECT 157.050 801.780 157.130 802.270 ;
        RECT 157.970 801.780 162.650 802.270 ;
        RECT 163.490 801.780 163.570 802.270 ;
        RECT 164.410 801.780 164.490 802.270 ;
        RECT 165.330 801.780 173.690 802.270 ;
        RECT 174.530 801.780 182.890 802.270 ;
        RECT 183.730 801.780 183.810 802.270 ;
        RECT 184.650 801.780 185.650 802.270 ;
        RECT 186.490 801.780 186.570 802.270 ;
        RECT 187.410 801.780 194.850 802.270 ;
        RECT 195.690 801.780 198.530 802.270 ;
        RECT 199.370 801.780 199.450 802.270 ;
        RECT 200.290 801.780 203.130 802.270 ;
        RECT 203.970 801.780 204.050 802.270 ;
        RECT 204.890 801.780 204.970 802.270 ;
        RECT 205.810 801.780 210.490 802.270 ;
        RECT 211.330 801.780 211.410 802.270 ;
        RECT 212.250 801.780 214.170 802.270 ;
        RECT 215.010 801.780 216.010 802.270 ;
        RECT 216.850 801.780 225.210 802.270 ;
        RECT 226.050 801.780 226.130 802.270 ;
        RECT 226.970 801.780 227.050 802.270 ;
        RECT 227.890 801.780 240.850 802.270 ;
        RECT 241.690 801.780 242.690 802.270 ;
        RECT 243.530 801.780 243.610 802.270 ;
        RECT 244.450 801.780 248.210 802.270 ;
        RECT 249.050 801.780 252.810 802.270 ;
        RECT 253.650 801.780 253.730 802.270 ;
        RECT 254.570 801.780 254.650 802.270 ;
        RECT 255.490 801.780 255.570 802.270 ;
        RECT 256.410 801.780 258.330 802.270 ;
        RECT 259.170 801.780 259.250 802.270 ;
        RECT 260.090 801.780 260.170 802.270 ;
        RECT 261.010 801.780 264.770 802.270 ;
        RECT 265.610 801.780 265.690 802.270 ;
        RECT 266.530 801.780 273.050 802.270 ;
        RECT 273.890 801.780 283.170 802.270 ;
        RECT 284.010 801.780 285.930 802.270 ;
        RECT 286.770 801.780 287.770 802.270 ;
        RECT 288.610 801.780 288.690 802.270 ;
        RECT 289.530 801.780 289.610 802.270 ;
        RECT 290.450 801.780 290.530 802.270 ;
        RECT 291.370 801.780 291.450 802.270 ;
        RECT 292.290 801.780 292.370 802.270 ;
        RECT 293.210 801.780 293.290 802.270 ;
        RECT 294.130 801.780 295.130 802.270 ;
        RECT 295.970 801.780 303.410 802.270 ;
        RECT 304.250 801.780 304.330 802.270 ;
        RECT 305.170 801.780 308.930 802.270 ;
        RECT 309.770 801.780 313.530 802.270 ;
        RECT 314.370 801.780 317.210 802.270 ;
        RECT 318.050 801.780 318.130 802.270 ;
        RECT 318.970 801.780 325.490 802.270 ;
        RECT 326.330 801.780 326.410 802.270 ;
        RECT 327.250 801.780 329.170 802.270 ;
        RECT 330.010 801.780 338.370 802.270 ;
        RECT 339.210 801.780 354.010 802.270 ;
        RECT 354.850 801.780 354.930 802.270 ;
        RECT 355.770 801.780 355.850 802.270 ;
        RECT 356.690 801.780 364.130 802.270 ;
        RECT 364.970 801.780 368.730 802.270 ;
        RECT 369.570 801.780 370.570 802.270 ;
        RECT 371.410 801.780 377.010 802.270 ;
        RECT 377.850 801.780 377.930 802.270 ;
        RECT 378.770 801.780 378.850 802.270 ;
        RECT 379.690 801.780 379.770 802.270 ;
        RECT 380.610 801.780 380.690 802.270 ;
        RECT 381.530 801.780 381.610 802.270 ;
        RECT 382.450 801.780 382.530 802.270 ;
        RECT 383.370 801.780 383.450 802.270 ;
        RECT 384.290 801.780 387.130 802.270 ;
        RECT 387.970 801.780 388.050 802.270 ;
        RECT 388.890 801.780 390.810 802.270 ;
        RECT 391.650 801.780 391.730 802.270 ;
        RECT 392.570 801.780 392.650 802.270 ;
        RECT 393.490 801.780 395.410 802.270 ;
        RECT 396.250 801.780 399.090 802.270 ;
        RECT 399.930 801.780 400.010 802.270 ;
        RECT 400.850 801.780 400.930 802.270 ;
        RECT 401.770 801.780 402.770 802.270 ;
        RECT 403.610 801.780 403.690 802.270 ;
        RECT 404.530 801.780 404.610 802.270 ;
        RECT 405.450 801.780 405.530 802.270 ;
        RECT 406.370 801.780 409.210 802.270 ;
        RECT 410.050 801.780 412.890 802.270 ;
        RECT 413.730 801.780 413.810 802.270 ;
        RECT 414.650 801.780 415.650 802.270 ;
        RECT 416.490 801.780 416.570 802.270 ;
        RECT 417.410 801.780 418.410 802.270 ;
        RECT 419.250 801.780 426.690 802.270 ;
        RECT 427.530 801.780 431.290 802.270 ;
        RECT 432.130 801.780 432.210 802.270 ;
        RECT 433.050 801.780 435.890 802.270 ;
        RECT 436.730 801.780 438.650 802.270 ;
        RECT 439.490 801.780 442.330 802.270 ;
        RECT 443.170 801.780 444.170 802.270 ;
        RECT 445.010 801.780 449.690 802.270 ;
        RECT 450.530 801.780 453.370 802.270 ;
        RECT 454.210 801.780 457.970 802.270 ;
        RECT 458.810 801.780 469.930 802.270 ;
        RECT 470.770 801.780 471.770 802.270 ;
        RECT 472.610 801.780 497.530 802.270 ;
        RECT 498.370 801.780 505.810 802.270 ;
        RECT 506.650 801.780 511.330 802.270 ;
        RECT 512.170 801.780 512.250 802.270 ;
        RECT 513.090 801.780 513.170 802.270 ;
        RECT 514.010 801.780 518.690 802.270 ;
        RECT 519.530 801.780 519.610 802.270 ;
        RECT 520.450 801.780 520.530 802.270 ;
        RECT 521.370 801.780 521.450 802.270 ;
        RECT 522.290 801.780 522.370 802.270 ;
        RECT 523.210 801.780 527.890 802.270 ;
        RECT 528.730 801.780 530.650 802.270 ;
        RECT 531.490 801.780 533.410 802.270 ;
        RECT 534.250 801.780 538.930 802.270 ;
        RECT 539.770 801.780 542.610 802.270 ;
        RECT 543.450 801.780 543.530 802.270 ;
        RECT 544.370 801.780 546.290 802.270 ;
        RECT 547.130 801.780 547.210 802.270 ;
        RECT 548.050 801.780 552.730 802.270 ;
        RECT 553.570 801.780 556.410 802.270 ;
        RECT 557.250 801.780 557.330 802.270 ;
        RECT 558.170 801.780 558.250 802.270 ;
        RECT 559.090 801.780 559.170 802.270 ;
        RECT 560.010 801.780 560.090 802.270 ;
        RECT 560.930 801.780 564.690 802.270 ;
        RECT 565.530 801.780 565.610 802.270 ;
        RECT 566.450 801.780 568.370 802.270 ;
        RECT 569.210 801.780 572.050 802.270 ;
        RECT 572.890 801.780 575.730 802.270 ;
        RECT 576.570 801.780 580.330 802.270 ;
        RECT 581.170 801.780 582.170 802.270 ;
        RECT 583.010 801.780 586.770 802.270 ;
        RECT 587.610 801.780 622.650 802.270 ;
        RECT 623.490 801.780 626.330 802.270 ;
        RECT 627.170 801.780 634.610 802.270 ;
        RECT 635.450 801.780 635.530 802.270 ;
        RECT 636.370 801.780 637.370 802.270 ;
        RECT 638.210 801.780 644.730 802.270 ;
        RECT 645.570 801.780 733.970 802.270 ;
        RECT 734.810 801.780 742.250 802.270 ;
        RECT 743.090 801.780 745.010 802.270 ;
        RECT 745.850 801.780 790.650 802.270 ;
        RECT 0.550 0.560 790.650 801.780 ;
        RECT 0.550 0.070 89.970 0.560 ;
        RECT 90.810 0.070 94.570 0.560 ;
        RECT 95.410 0.070 105.610 0.560 ;
        RECT 106.450 0.070 117.570 0.560 ;
        RECT 118.410 0.070 132.290 0.560 ;
        RECT 133.130 0.070 140.570 0.560 ;
        RECT 141.410 0.070 161.730 0.560 ;
        RECT 162.570 0.070 171.850 0.560 ;
        RECT 172.690 0.070 211.410 0.560 ;
        RECT 212.250 0.070 212.330 0.560 ;
        RECT 213.170 0.070 216.010 0.560 ;
        RECT 216.850 0.070 217.850 0.560 ;
        RECT 218.690 0.070 233.490 0.560 ;
        RECT 234.330 0.070 236.250 0.560 ;
        RECT 237.090 0.070 238.090 0.560 ;
        RECT 238.930 0.070 243.610 0.560 ;
        RECT 244.450 0.070 245.450 0.560 ;
        RECT 246.290 0.070 248.210 0.560 ;
        RECT 249.050 0.070 250.050 0.560 ;
        RECT 250.890 0.070 256.490 0.560 ;
        RECT 257.330 0.070 260.170 0.560 ;
        RECT 261.010 0.070 261.090 0.560 ;
        RECT 261.930 0.070 263.850 0.560 ;
        RECT 264.690 0.070 273.050 0.560 ;
        RECT 273.890 0.070 274.890 0.560 ;
        RECT 275.730 0.070 277.650 0.560 ;
        RECT 278.490 0.070 278.570 0.560 ;
        RECT 279.410 0.070 279.490 0.560 ;
        RECT 280.330 0.070 281.330 0.560 ;
        RECT 282.170 0.070 282.250 0.560 ;
        RECT 283.090 0.070 285.010 0.560 ;
        RECT 285.850 0.070 285.930 0.560 ;
        RECT 286.770 0.070 296.050 0.560 ;
        RECT 296.890 0.070 296.970 0.560 ;
        RECT 297.810 0.070 305.250 0.560 ;
        RECT 306.090 0.070 307.090 0.560 ;
        RECT 307.930 0.070 308.010 0.560 ;
        RECT 308.850 0.070 314.450 0.560 ;
        RECT 315.290 0.070 317.210 0.560 ;
        RECT 318.050 0.070 318.130 0.560 ;
        RECT 318.970 0.070 320.890 0.560 ;
        RECT 321.730 0.070 321.810 0.560 ;
        RECT 322.650 0.070 322.730 0.560 ;
        RECT 323.570 0.070 323.650 0.560 ;
        RECT 324.490 0.070 327.330 0.560 ;
        RECT 328.170 0.070 329.170 0.560 ;
        RECT 330.010 0.070 330.090 0.560 ;
        RECT 330.930 0.070 336.530 0.560 ;
        RECT 337.370 0.070 338.370 0.560 ;
        RECT 339.210 0.070 355.850 0.560 ;
        RECT 356.690 0.070 356.770 0.560 ;
        RECT 357.610 0.070 358.610 0.560 ;
        RECT 359.450 0.070 359.530 0.560 ;
        RECT 360.370 0.070 360.450 0.560 ;
        RECT 361.290 0.070 361.370 0.560 ;
        RECT 362.210 0.070 362.290 0.560 ;
        RECT 363.130 0.070 363.210 0.560 ;
        RECT 364.050 0.070 364.130 0.560 ;
        RECT 364.970 0.070 365.050 0.560 ;
        RECT 365.890 0.070 365.970 0.560 ;
        RECT 366.810 0.070 366.890 0.560 ;
        RECT 367.730 0.070 367.810 0.560 ;
        RECT 368.650 0.070 368.730 0.560 ;
        RECT 369.570 0.070 376.090 0.560 ;
        RECT 376.930 0.070 377.010 0.560 ;
        RECT 377.850 0.070 377.930 0.560 ;
        RECT 378.770 0.070 378.850 0.560 ;
        RECT 379.690 0.070 379.770 0.560 ;
        RECT 380.610 0.070 380.690 0.560 ;
        RECT 381.530 0.070 381.610 0.560 ;
        RECT 382.450 0.070 382.530 0.560 ;
        RECT 383.370 0.070 383.450 0.560 ;
        RECT 384.290 0.070 384.370 0.560 ;
        RECT 385.210 0.070 386.210 0.560 ;
        RECT 387.050 0.070 387.130 0.560 ;
        RECT 387.970 0.070 391.730 0.560 ;
        RECT 392.570 0.070 395.410 0.560 ;
        RECT 396.250 0.070 403.690 0.560 ;
        RECT 404.530 0.070 410.130 0.560 ;
        RECT 410.970 0.070 411.050 0.560 ;
        RECT 411.890 0.070 413.810 0.560 ;
        RECT 414.650 0.070 419.330 0.560 ;
        RECT 420.170 0.070 420.250 0.560 ;
        RECT 421.090 0.070 433.130 0.560 ;
        RECT 433.970 0.070 436.810 0.560 ;
        RECT 437.650 0.070 439.570 0.560 ;
        RECT 440.410 0.070 440.490 0.560 ;
        RECT 441.330 0.070 444.170 0.560 ;
        RECT 445.010 0.070 450.610 0.560 ;
        RECT 451.450 0.070 451.530 0.560 ;
        RECT 452.370 0.070 454.290 0.560 ;
        RECT 455.130 0.070 455.210 0.560 ;
        RECT 456.050 0.070 456.130 0.560 ;
        RECT 456.970 0.070 458.890 0.560 ;
        RECT 459.730 0.070 463.490 0.560 ;
        RECT 464.330 0.070 464.410 0.560 ;
        RECT 465.250 0.070 465.330 0.560 ;
        RECT 466.170 0.070 466.250 0.560 ;
        RECT 467.090 0.070 467.170 0.560 ;
        RECT 468.010 0.070 469.930 0.560 ;
        RECT 470.770 0.070 470.850 0.560 ;
        RECT 471.690 0.070 472.690 0.560 ;
        RECT 473.530 0.070 473.610 0.560 ;
        RECT 474.450 0.070 474.530 0.560 ;
        RECT 475.370 0.070 475.450 0.560 ;
        RECT 476.290 0.070 476.370 0.560 ;
        RECT 477.210 0.070 477.290 0.560 ;
        RECT 478.130 0.070 478.210 0.560 ;
        RECT 479.050 0.070 484.650 0.560 ;
        RECT 485.490 0.070 485.570 0.560 ;
        RECT 486.410 0.070 486.490 0.560 ;
        RECT 487.330 0.070 487.410 0.560 ;
        RECT 488.250 0.070 492.010 0.560 ;
        RECT 492.850 0.070 492.930 0.560 ;
        RECT 493.770 0.070 493.850 0.560 ;
        RECT 494.690 0.070 494.770 0.560 ;
        RECT 495.610 0.070 496.610 0.560 ;
        RECT 497.450 0.070 497.530 0.560 ;
        RECT 498.370 0.070 503.970 0.560 ;
        RECT 504.810 0.070 504.890 0.560 ;
        RECT 505.730 0.070 505.810 0.560 ;
        RECT 506.650 0.070 509.490 0.560 ;
        RECT 510.330 0.070 512.250 0.560 ;
        RECT 513.090 0.070 514.090 0.560 ;
        RECT 514.930 0.070 515.010 0.560 ;
        RECT 515.850 0.070 524.210 0.560 ;
        RECT 525.050 0.070 526.050 0.560 ;
        RECT 526.890 0.070 527.890 0.560 ;
        RECT 528.730 0.070 555.490 0.560 ;
        RECT 556.330 0.070 571.130 0.560 ;
        RECT 571.970 0.070 580.330 0.560 ;
        RECT 581.170 0.070 585.850 0.560 ;
        RECT 586.690 0.070 586.770 0.560 ;
        RECT 587.610 0.070 593.210 0.560 ;
        RECT 594.050 0.070 594.130 0.560 ;
        RECT 594.970 0.070 604.250 0.560 ;
        RECT 605.090 0.070 606.090 0.560 ;
        RECT 606.930 0.070 607.010 0.560 ;
        RECT 607.850 0.070 617.130 0.560 ;
        RECT 617.970 0.070 619.890 0.560 ;
        RECT 620.730 0.070 625.410 0.560 ;
        RECT 626.250 0.070 634.610 0.560 ;
        RECT 635.450 0.070 635.530 0.560 ;
        RECT 636.370 0.070 641.970 0.560 ;
        RECT 642.810 0.070 642.890 0.560 ;
        RECT 643.730 0.070 643.810 0.560 ;
        RECT 644.650 0.070 644.730 0.560 ;
        RECT 645.570 0.070 645.650 0.560 ;
        RECT 646.490 0.070 647.490 0.560 ;
        RECT 648.330 0.070 648.410 0.560 ;
        RECT 649.250 0.070 790.650 0.560 ;
      LAYER met3 ;
        RECT 0.525 784.400 791.020 794.745 ;
        RECT 1.000 783.000 791.020 784.400 ;
        RECT 0.525 713.680 791.020 783.000 ;
        RECT 1.000 710.920 791.020 713.680 ;
        RECT 0.525 689.200 791.020 710.920 ;
        RECT 1.000 687.800 791.020 689.200 ;
        RECT 0.525 685.120 791.020 687.800 ;
        RECT 1.000 683.720 791.020 685.120 ;
        RECT 0.525 678.320 791.020 683.720 ;
        RECT 1.000 675.560 791.020 678.320 ;
        RECT 0.525 670.160 791.020 675.560 ;
        RECT 0.525 668.760 790.620 670.160 ;
        RECT 0.525 664.720 791.020 668.760 ;
        RECT 1.000 662.000 791.020 664.720 ;
        RECT 1.000 661.960 790.620 662.000 ;
        RECT 0.525 659.280 790.620 661.960 ;
        RECT 1.000 659.240 790.620 659.280 ;
        RECT 1.000 657.880 791.020 659.240 ;
        RECT 0.525 653.840 791.020 657.880 ;
        RECT 1.000 652.440 791.020 653.840 ;
        RECT 0.525 651.120 791.020 652.440 ;
        RECT 0.525 649.720 790.620 651.120 ;
        RECT 0.525 642.960 791.020 649.720 ;
        RECT 0.525 638.840 790.620 642.960 ;
        RECT 0.525 637.520 791.020 638.840 ;
        RECT 1.000 636.120 790.620 637.520 ;
        RECT 1.000 634.760 791.020 636.120 ;
        RECT 0.525 633.440 791.020 634.760 ;
        RECT 0.525 632.080 790.620 633.440 ;
        RECT 1.000 630.680 790.620 632.080 ;
        RECT 0.525 629.320 790.620 630.680 ;
        RECT 0.525 626.640 791.020 629.320 ;
        RECT 1.000 623.920 791.020 626.640 ;
        RECT 1.000 623.880 790.620 623.920 ;
        RECT 0.525 622.560 790.620 623.880 ;
        RECT 1.000 621.160 790.620 622.560 ;
        RECT 1.000 619.800 791.020 621.160 ;
        RECT 0.525 611.680 791.020 619.800 ;
        RECT 0.525 610.280 790.620 611.680 ;
        RECT 0.525 608.960 791.020 610.280 ;
        RECT 1.000 606.200 791.020 608.960 ;
        RECT 0.525 603.520 791.020 606.200 ;
        RECT 0.525 602.120 790.620 603.520 ;
        RECT 0.525 600.800 791.020 602.120 ;
        RECT 1.000 599.400 791.020 600.800 ;
        RECT 0.525 596.720 791.020 599.400 ;
        RECT 0.525 595.360 790.620 596.720 ;
        RECT 1.000 595.320 790.620 595.360 ;
        RECT 1.000 593.960 791.020 595.320 ;
        RECT 0.525 589.920 791.020 593.960 ;
        RECT 1.000 588.520 791.020 589.920 ;
        RECT 0.525 577.680 791.020 588.520 ;
        RECT 1.000 576.320 791.020 577.680 ;
        RECT 1.000 576.280 790.620 576.320 ;
        RECT 0.525 573.600 790.620 576.280 ;
        RECT 1.000 572.200 790.620 573.600 ;
        RECT 0.525 570.880 790.620 572.200 ;
        RECT 1.000 568.120 790.620 570.880 ;
        RECT 1.000 566.760 791.020 568.120 ;
        RECT 0.525 565.440 791.020 566.760 ;
        RECT 1.000 564.040 791.020 565.440 ;
        RECT 0.525 562.720 791.020 564.040 ;
        RECT 0.525 561.320 790.620 562.720 ;
        RECT 0.525 557.280 791.020 561.320 ;
        RECT 1.000 555.920 791.020 557.280 ;
        RECT 1.000 555.880 790.620 555.920 ;
        RECT 0.525 554.520 790.620 555.880 ;
        RECT 0.525 553.200 791.020 554.520 ;
        RECT 1.000 551.800 791.020 553.200 ;
        RECT 0.525 549.120 791.020 551.800 ;
        RECT 1.000 547.720 791.020 549.120 ;
        RECT 0.525 545.040 791.020 547.720 ;
        RECT 1.000 543.640 791.020 545.040 ;
        RECT 0.525 536.880 791.020 543.640 ;
        RECT 1.000 535.480 791.020 536.880 ;
        RECT 0.525 528.720 791.020 535.480 ;
        RECT 1.000 527.320 791.020 528.720 ;
        RECT 0.525 526.000 791.020 527.320 ;
        RECT 0.525 521.920 790.620 526.000 ;
        RECT 1.000 520.520 790.620 521.920 ;
        RECT 0.525 516.480 791.020 520.520 ;
        RECT 1.000 515.080 791.020 516.480 ;
        RECT 0.525 511.040 791.020 515.080 ;
        RECT 1.000 509.640 791.020 511.040 ;
        RECT 0.525 506.960 791.020 509.640 ;
        RECT 1.000 505.560 791.020 506.960 ;
        RECT 0.525 504.240 791.020 505.560 ;
        RECT 1.000 498.800 791.020 504.240 ;
        RECT 1.000 498.760 790.620 498.800 ;
        RECT 0.525 497.440 790.620 498.760 ;
        RECT 1.000 497.400 790.620 497.440 ;
        RECT 1.000 496.040 791.020 497.400 ;
        RECT 0.525 489.280 791.020 496.040 ;
        RECT 1.000 487.880 791.020 489.280 ;
        RECT 0.525 486.560 791.020 487.880 ;
        RECT 1.000 485.160 791.020 486.560 ;
        RECT 0.525 481.120 791.020 485.160 ;
        RECT 1.000 478.360 791.020 481.120 ;
        RECT 0.525 474.320 791.020 478.360 ;
        RECT 0.525 472.960 790.620 474.320 ;
        RECT 1.000 472.920 790.620 472.960 ;
        RECT 1.000 467.480 791.020 472.920 ;
        RECT 0.525 466.160 791.020 467.480 ;
        RECT 1.000 464.760 791.020 466.160 ;
        RECT 0.525 462.080 791.020 464.760 ;
        RECT 0.525 460.680 790.620 462.080 ;
        RECT 0.525 459.360 791.020 460.680 ;
        RECT 1.000 457.960 790.620 459.360 ;
        RECT 1.000 453.880 791.020 457.960 ;
        RECT 0.525 447.120 791.020 453.880 ;
        RECT 1.000 444.360 791.020 447.120 ;
        RECT 0.525 440.320 791.020 444.360 ;
        RECT 1.000 438.920 791.020 440.320 ;
        RECT 0.525 436.240 791.020 438.920 ;
        RECT 1.000 434.840 790.620 436.240 ;
        RECT 1.000 433.520 791.020 434.840 ;
        RECT 1.000 432.120 790.620 433.520 ;
        RECT 1.000 430.760 791.020 432.120 ;
        RECT 0.525 429.440 791.020 430.760 ;
        RECT 1.000 422.600 791.020 429.440 ;
        RECT 0.525 419.920 791.020 422.600 ;
        RECT 1.000 418.520 791.020 419.920 ;
        RECT 0.525 417.200 791.020 418.520 ;
        RECT 0.525 415.840 790.620 417.200 ;
        RECT 1.000 415.800 790.620 415.840 ;
        RECT 1.000 414.440 791.020 415.800 ;
        RECT 0.525 413.120 791.020 414.440 ;
        RECT 0.525 411.720 790.620 413.120 ;
        RECT 0.525 410.400 791.020 411.720 ;
        RECT 1.000 409.000 790.620 410.400 ;
        RECT 0.525 406.320 791.020 409.000 ;
        RECT 1.000 404.920 791.020 406.320 ;
        RECT 0.525 403.600 791.020 404.920 ;
        RECT 0.525 402.240 790.620 403.600 ;
        RECT 1.000 402.200 790.620 402.240 ;
        RECT 1.000 400.880 791.020 402.200 ;
        RECT 1.000 400.840 790.620 400.880 ;
        RECT 0.525 396.800 790.620 400.840 ;
        RECT 1.000 395.400 790.620 396.800 ;
        RECT 0.525 394.080 790.620 395.400 ;
        RECT 1.000 394.040 790.620 394.080 ;
        RECT 1.000 392.720 791.020 394.040 ;
        RECT 1.000 392.680 790.620 392.720 ;
        RECT 0.525 391.360 790.620 392.680 ;
        RECT 1.000 391.320 790.620 391.360 ;
        RECT 1.000 390.000 791.020 391.320 ;
        RECT 1.000 389.960 790.620 390.000 ;
        RECT 0.525 387.280 790.620 389.960 ;
        RECT 1.000 385.880 790.620 387.280 ;
        RECT 0.525 384.560 790.620 385.880 ;
        RECT 1.000 383.160 790.620 384.560 ;
        RECT 0.525 377.760 790.620 383.160 ;
        RECT 1.000 376.360 790.620 377.760 ;
        RECT 1.000 373.680 791.020 376.360 ;
        RECT 1.000 373.640 790.620 373.680 ;
        RECT 0.525 372.320 790.620 373.640 ;
        RECT 1.000 370.920 790.620 372.320 ;
        RECT 0.525 369.560 790.620 370.920 ;
        RECT 0.525 366.880 791.020 369.560 ;
        RECT 1.000 365.480 791.020 366.880 ;
        RECT 0.525 362.800 791.020 365.480 ;
        RECT 0.525 361.440 790.620 362.800 ;
        RECT 1.000 361.400 790.620 361.440 ;
        RECT 1.000 360.080 791.020 361.400 ;
        RECT 1.000 360.040 790.620 360.080 ;
        RECT 0.525 358.720 790.620 360.040 ;
        RECT 1.000 358.680 790.620 358.720 ;
        RECT 1.000 357.320 791.020 358.680 ;
        RECT 0.525 356.000 791.020 357.320 ;
        RECT 1.000 353.280 791.020 356.000 ;
        RECT 1.000 351.880 790.620 353.280 ;
        RECT 0.525 349.200 790.620 351.880 ;
        RECT 1.000 349.160 790.620 349.200 ;
        RECT 1.000 346.480 791.020 349.160 ;
        RECT 1.000 346.440 790.620 346.480 ;
        RECT 0.525 345.080 790.620 346.440 ;
        RECT 0.525 341.040 791.020 345.080 ;
        RECT 0.525 338.280 790.620 341.040 ;
        RECT 0.525 335.600 791.020 338.280 ;
        RECT 0.525 334.240 790.620 335.600 ;
        RECT 1.000 332.840 790.620 334.240 ;
        RECT 0.525 331.480 790.620 332.840 ;
        RECT 0.525 330.160 791.020 331.480 ;
        RECT 0.525 328.760 790.620 330.160 ;
        RECT 0.525 327.440 791.020 328.760 ;
        RECT 1.000 326.040 791.020 327.440 ;
        RECT 0.525 323.360 791.020 326.040 ;
        RECT 0.525 322.000 790.620 323.360 ;
        RECT 1.000 321.960 790.620 322.000 ;
        RECT 1.000 319.280 791.020 321.960 ;
        RECT 1.000 317.880 790.620 319.280 ;
        RECT 0.525 315.200 791.020 317.880 ;
        RECT 1.000 313.800 791.020 315.200 ;
        RECT 0.525 312.480 791.020 313.800 ;
        RECT 0.525 311.120 790.620 312.480 ;
        RECT 1.000 311.080 790.620 311.120 ;
        RECT 1.000 309.760 791.020 311.080 ;
        RECT 1.000 308.360 790.620 309.760 ;
        RECT 0.525 307.040 790.620 308.360 ;
        RECT 1.000 305.640 790.620 307.040 ;
        RECT 0.525 304.280 790.620 305.640 ;
        RECT 0.525 296.160 791.020 304.280 ;
        RECT 0.525 294.760 790.620 296.160 ;
        RECT 0.525 283.920 791.020 294.760 ;
        RECT 1.000 282.520 791.020 283.920 ;
        RECT 0.525 281.200 791.020 282.520 ;
        RECT 1.000 279.800 790.620 281.200 ;
        RECT 1.000 277.080 791.020 279.800 ;
        RECT 0.525 273.040 791.020 277.080 ;
        RECT 1.000 271.640 790.620 273.040 ;
        RECT 1.000 268.920 791.020 271.640 ;
        RECT 0.525 263.520 791.020 268.920 ;
        RECT 1.000 262.120 790.620 263.520 ;
        RECT 0.525 260.800 791.020 262.120 ;
        RECT 0.525 259.400 790.620 260.800 ;
        RECT 0.525 256.720 791.020 259.400 ;
        RECT 1.000 255.320 791.020 256.720 ;
        RECT 0.525 252.640 791.020 255.320 ;
        RECT 1.000 251.240 790.620 252.640 ;
        RECT 0.525 249.880 790.620 251.240 ;
        RECT 0.525 244.480 791.020 249.880 ;
        RECT 0.525 243.120 790.620 244.480 ;
        RECT 1.000 241.720 790.620 243.120 ;
        RECT 0.525 239.040 791.020 241.720 ;
        RECT 1.000 237.680 791.020 239.040 ;
        RECT 1.000 236.280 790.620 237.680 ;
        RECT 0.525 234.960 791.020 236.280 ;
        RECT 1.000 233.560 790.620 234.960 ;
        RECT 0.525 228.160 791.020 233.560 ;
        RECT 1.000 226.760 791.020 228.160 ;
        RECT 0.525 213.200 791.020 226.760 ;
        RECT 1.000 211.800 791.020 213.200 ;
        RECT 0.525 210.480 791.020 211.800 ;
        RECT 1.000 209.080 791.020 210.480 ;
        RECT 0.525 202.320 791.020 209.080 ;
        RECT 1.000 200.920 791.020 202.320 ;
        RECT 0.525 192.800 791.020 200.920 ;
        RECT 1.000 191.400 791.020 192.800 ;
        RECT 0.525 190.080 791.020 191.400 ;
        RECT 1.000 185.960 791.020 190.080 ;
        RECT 0.525 179.200 791.020 185.960 ;
        RECT 1.000 177.800 791.020 179.200 ;
        RECT 0.525 171.040 791.020 177.800 ;
        RECT 1.000 169.640 791.020 171.040 ;
        RECT 0.525 150.640 791.020 169.640 ;
        RECT 1.000 149.240 791.020 150.640 ;
        RECT 0.525 145.200 791.020 149.240 ;
        RECT 0.525 143.800 790.620 145.200 ;
        RECT 0.525 141.120 791.020 143.800 ;
        RECT 1.000 139.760 791.020 141.120 ;
        RECT 1.000 139.720 790.620 139.760 ;
        RECT 0.525 138.400 790.620 139.720 ;
        RECT 1.000 138.360 790.620 138.400 ;
        RECT 1.000 135.640 791.020 138.360 ;
        RECT 0.525 127.520 791.020 135.640 ;
        RECT 1.000 124.760 791.020 127.520 ;
        RECT 0.525 97.600 791.020 124.760 ;
        RECT 0.525 96.200 790.620 97.600 ;
        RECT 0.525 37.760 791.020 96.200 ;
        RECT 0.525 36.360 790.620 37.760 ;
        RECT 0.525 6.975 791.020 36.360 ;
      LAYER met4 ;
        RECT 5.815 10.240 20.640 788.625 ;
        RECT 23.040 10.240 23.940 788.625 ;
        RECT 26.340 10.240 174.240 788.625 ;
        RECT 176.640 10.240 177.540 788.625 ;
        RECT 179.940 10.240 327.840 788.625 ;
        RECT 330.240 10.240 331.140 788.625 ;
        RECT 333.540 10.240 481.440 788.625 ;
        RECT 483.840 10.240 484.740 788.625 ;
        RECT 487.140 10.240 635.040 788.625 ;
        RECT 637.440 10.240 638.340 788.625 ;
        RECT 640.740 10.240 783.545 788.625 ;
        RECT 5.815 9.015 783.545 10.240 ;
      LAYER met5 ;
        RECT 33.700 645.950 779.580 787.900 ;
        RECT 33.700 492.770 779.580 637.850 ;
        RECT 33.700 339.590 779.580 484.670 ;
        RECT 33.700 186.410 779.580 331.490 ;
        RECT 33.700 38.300 779.580 178.310 ;
  END
END aes_core_256
END LIBRARY

